VERSION 5.7 ;
  NOWIREEXTENSIONATPIN ON ;
  DIVIDERCHAR "/" ;
  BUSBITCHARS "[]" ;
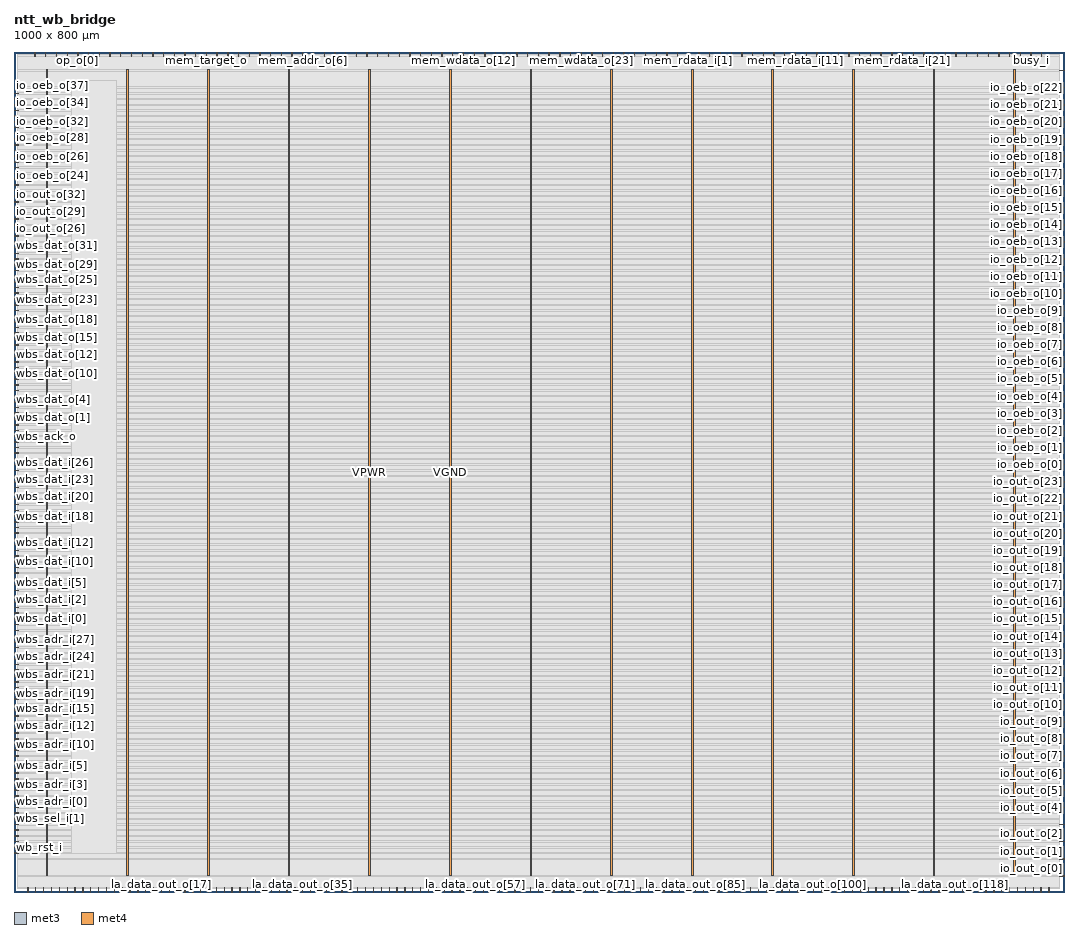
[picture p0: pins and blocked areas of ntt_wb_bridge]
MACRO ntt_wb_bridge
  CLASS BLOCK ;
  FOREIGN ntt_wb_bridge ;
  ORIGIN 0.000 0.000 ;
  SIZE 1000.000 BY 800.000 ;
  PIN VGND
    DIRECTION INOUT ;
    USE GROUND ;
    PORT
      LAYER met3 ;
        RECT 30.110 796.000 30.410 800.000 ;
    END
    PORT
      LAYER met4 ;
        RECT 107.500 16.080 109.100 783.600 ;
    END
    PORT
      LAYER met4 ;
        RECT 261.100 16.080 262.700 783.600 ;
    END
    PORT
      LAYER met4 ;
        RECT 414.700 16.080 416.300 783.600 ;
    END
    PORT
      LAYER met4 ;
        RECT 568.300 16.080 569.900 783.600 ;
    END
    PORT
      LAYER met4 ;
        RECT 721.900 16.080 723.500 783.600 ;
    END
    PORT
      LAYER met4 ;
        RECT 875.500 16.080 877.100 783.600 ;
    END
  END VGND
  PIN VPWR
    DIRECTION INOUT ;
    USE POWER ;
    PORT
      LAYER met3 ;
        RECT 19.910 796.000 20.210 800.000 ;
    END
    PORT
      LAYER met4 ;
        RECT 30.700 16.080 32.300 783.600 ;
    END
    PORT
      LAYER met4 ;
        RECT 184.300 16.080 185.900 783.600 ;
    END
    PORT
      LAYER met4 ;
        RECT 337.900 16.080 339.500 783.600 ;
    END
    PORT
      LAYER met4 ;
        RECT 491.500 16.080 493.100 783.600 ;
    END
    PORT
      LAYER met4 ;
        RECT 645.100 16.080 646.700 783.600 ;
    END
    PORT
      LAYER met4 ;
        RECT 798.700 16.080 800.300 783.600 ;
    END
    PORT
      LAYER met4 ;
        RECT 952.300 16.080 953.900 783.600 ;
    END
  END VPWR
  PIN busy_i
    DIRECTION INPUT ;
    USE SIGNAL ;
    ANTENNAGATEAREA 0.196500 ;
    ANTENNADIFFAREA 0.434700 ;
    PORT
      LAYER met3 ;
        RECT 968.510 796.000 968.810 800.000 ;
    END
  END busy_i
  PIN done_i
    DIRECTION INPUT ;
    USE SIGNAL ;
    ANTENNAGATEAREA 0.196500 ;
    ANTENNADIFFAREA 0.434700 ;
    PORT
      LAYER met3 ;
        RECT 978.710 796.000 979.010 800.000 ;
    END
  END done_i
  PIN engine_rst_n_o
    DIRECTION OUTPUT TRISTATE ;
    USE SIGNAL ;
    ANTENNADIFFAREA 3.180800 ;
    PORT
      LAYER met3 ;
        RECT 50.510 796.000 50.810 800.000 ;
    END
  END engine_rst_n_o
  PIN io_oeb_o[0]
    DIRECTION OUTPUT TRISTATE ;
    USE SIGNAL ;
    PORT
      LAYER met3 ;
        RECT 996.000 406.680 1000.000 407.280 ;
    END
  END io_oeb_o[0]
  PIN io_oeb_o[10]
    DIRECTION OUTPUT TRISTATE ;
    USE SIGNAL ;
    PORT
      LAYER met3 ;
        RECT 996.000 569.880 1000.000 570.480 ;
    END
  END io_oeb_o[10]
  PIN io_oeb_o[11]
    DIRECTION OUTPUT TRISTATE ;
    USE SIGNAL ;
    PORT
      LAYER met3 ;
        RECT 996.000 586.200 1000.000 586.800 ;
    END
  END io_oeb_o[11]
  PIN io_oeb_o[12]
    DIRECTION OUTPUT TRISTATE ;
    USE SIGNAL ;
    PORT
      LAYER met3 ;
        RECT 996.000 602.520 1000.000 603.120 ;
    END
  END io_oeb_o[12]
  PIN io_oeb_o[13]
    DIRECTION OUTPUT TRISTATE ;
    USE SIGNAL ;
    PORT
      LAYER met3 ;
        RECT 996.000 618.840 1000.000 619.440 ;
    END
  END io_oeb_o[13]
  PIN io_oeb_o[14]
    DIRECTION OUTPUT TRISTATE ;
    USE SIGNAL ;
    PORT
      LAYER met3 ;
        RECT 996.000 635.160 1000.000 635.760 ;
    END
  END io_oeb_o[14]
  PIN io_oeb_o[15]
    DIRECTION OUTPUT TRISTATE ;
    USE SIGNAL ;
    PORT
      LAYER met3 ;
        RECT 996.000 651.480 1000.000 652.080 ;
    END
  END io_oeb_o[15]
  PIN io_oeb_o[16]
    DIRECTION OUTPUT TRISTATE ;
    USE SIGNAL ;
    PORT
      LAYER met3 ;
        RECT 996.000 667.800 1000.000 668.400 ;
    END
  END io_oeb_o[16]
  PIN io_oeb_o[17]
    DIRECTION OUTPUT TRISTATE ;
    USE SIGNAL ;
    PORT
      LAYER met3 ;
        RECT 996.000 684.120 1000.000 684.720 ;
    END
  END io_oeb_o[17]
  PIN io_oeb_o[18]
    DIRECTION OUTPUT TRISTATE ;
    USE SIGNAL ;
    PORT
      LAYER met3 ;
        RECT 996.000 700.440 1000.000 701.040 ;
    END
  END io_oeb_o[18]
  PIN io_oeb_o[19]
    DIRECTION OUTPUT TRISTATE ;
    USE SIGNAL ;
    PORT
      LAYER met3 ;
        RECT 996.000 716.760 1000.000 717.360 ;
    END
  END io_oeb_o[19]
  PIN io_oeb_o[1]
    DIRECTION OUTPUT TRISTATE ;
    USE SIGNAL ;
    PORT
      LAYER met3 ;
        RECT 996.000 423.000 1000.000 423.600 ;
    END
  END io_oeb_o[1]
  PIN io_oeb_o[20]
    DIRECTION OUTPUT TRISTATE ;
    USE SIGNAL ;
    PORT
      LAYER met3 ;
        RECT 996.000 733.080 1000.000 733.680 ;
    END
  END io_oeb_o[20]
  PIN io_oeb_o[21]
    DIRECTION OUTPUT TRISTATE ;
    USE SIGNAL ;
    PORT
      LAYER met3 ;
        RECT 996.000 749.400 1000.000 750.000 ;
    END
  END io_oeb_o[21]
  PIN io_oeb_o[22]
    DIRECTION OUTPUT TRISTATE ;
    USE SIGNAL ;
    PORT
      LAYER met3 ;
        RECT 996.000 765.720 1000.000 766.320 ;
    END
  END io_oeb_o[22]
  PIN io_oeb_o[23]
    DIRECTION OUTPUT TRISTATE ;
    USE SIGNAL ;
    PORT
      LAYER met3 ;
        RECT 996.000 782.040 1000.000 782.640 ;
    END
  END io_oeb_o[23]
  PIN io_oeb_o[24]
    DIRECTION OUTPUT TRISTATE ;
    USE SIGNAL ;
    PORT
      LAYER met3 ;
        RECT 0.000 689.560 4.000 690.160 ;
    END
  END io_oeb_o[24]
  PIN io_oeb_o[25]
    DIRECTION OUTPUT TRISTATE ;
    USE SIGNAL ;
    PORT
      LAYER met3 ;
        RECT 0.000 695.000 4.000 695.600 ;
    END
  END io_oeb_o[25]
  PIN io_oeb_o[26]
    DIRECTION OUTPUT TRISTATE ;
    USE SIGNAL ;
    PORT
      LAYER met3 ;
        RECT 0.000 700.440 4.000 701.040 ;
    END
  END io_oeb_o[26]
  PIN io_oeb_o[27]
    DIRECTION OUTPUT TRISTATE ;
    USE SIGNAL ;
    PORT
      LAYER met3 ;
        RECT 0.000 705.880 4.000 706.480 ;
    END
  END io_oeb_o[27]
  PIN io_oeb_o[28]
    DIRECTION OUTPUT TRISTATE ;
    USE SIGNAL ;
    PORT
      LAYER met3 ;
        RECT 0.000 711.320 4.000 711.920 ;
    END
  END io_oeb_o[28]
  PIN io_oeb_o[29]
    DIRECTION OUTPUT TRISTATE ;
    USE SIGNAL ;
    PORT
      LAYER met3 ;
        RECT 0.000 716.760 4.000 717.360 ;
    END
  END io_oeb_o[29]
  PIN io_oeb_o[2]
    DIRECTION OUTPUT TRISTATE ;
    USE SIGNAL ;
    PORT
      LAYER met3 ;
        RECT 996.000 439.320 1000.000 439.920 ;
    END
  END io_oeb_o[2]
  PIN io_oeb_o[30]
    DIRECTION OUTPUT TRISTATE ;
    USE SIGNAL ;
    PORT
      LAYER met3 ;
        RECT 0.000 722.200 4.000 722.800 ;
    END
  END io_oeb_o[30]
  PIN io_oeb_o[31]
    DIRECTION OUTPUT TRISTATE ;
    USE SIGNAL ;
    PORT
      LAYER met3 ;
        RECT 0.000 727.640 4.000 728.240 ;
    END
  END io_oeb_o[31]
  PIN io_oeb_o[32]
    DIRECTION OUTPUT TRISTATE ;
    USE SIGNAL ;
    PORT
      LAYER met3 ;
        RECT 0.000 733.080 4.000 733.680 ;
    END
  END io_oeb_o[32]
  PIN io_oeb_o[33]
    DIRECTION OUTPUT TRISTATE ;
    USE SIGNAL ;
    PORT
      LAYER met3 ;
        RECT 0.000 738.520 4.000 739.120 ;
    END
  END io_oeb_o[33]
  PIN io_oeb_o[34]
    DIRECTION OUTPUT TRISTATE ;
    USE SIGNAL ;
    PORT
      LAYER met3 ;
        RECT 0.000 743.960 4.000 744.560 ;
    END
  END io_oeb_o[34]
  PIN io_oeb_o[35]
    DIRECTION OUTPUT TRISTATE ;
    USE SIGNAL ;
    PORT
      LAYER met3 ;
        RECT 0.000 749.400 4.000 750.000 ;
    END
  END io_oeb_o[35]
  PIN io_oeb_o[36]
    DIRECTION OUTPUT TRISTATE ;
    USE SIGNAL ;
    PORT
      LAYER met3 ;
        RECT 0.000 754.840 4.000 755.440 ;
    END
  END io_oeb_o[36]
  PIN io_oeb_o[37]
    DIRECTION OUTPUT TRISTATE ;
    USE SIGNAL ;
    PORT
      LAYER met3 ;
        RECT 0.000 760.280 4.000 760.880 ;
    END
  END io_oeb_o[37]
  PIN io_oeb_o[3]
    DIRECTION OUTPUT TRISTATE ;
    USE SIGNAL ;
    PORT
      LAYER met3 ;
        RECT 996.000 455.640 1000.000 456.240 ;
    END
  END io_oeb_o[3]
  PIN io_oeb_o[4]
    DIRECTION OUTPUT TRISTATE ;
    USE SIGNAL ;
    PORT
      LAYER met3 ;
        RECT 996.000 471.960 1000.000 472.560 ;
    END
  END io_oeb_o[4]
  PIN io_oeb_o[5]
    DIRECTION OUTPUT TRISTATE ;
    USE SIGNAL ;
    PORT
      LAYER met3 ;
        RECT 996.000 488.280 1000.000 488.880 ;
    END
  END io_oeb_o[5]
  PIN io_oeb_o[6]
    DIRECTION OUTPUT TRISTATE ;
    USE SIGNAL ;
    PORT
      LAYER met3 ;
        RECT 996.000 504.600 1000.000 505.200 ;
    END
  END io_oeb_o[6]
  PIN io_oeb_o[7]
    DIRECTION OUTPUT TRISTATE ;
    USE SIGNAL ;
    PORT
      LAYER met3 ;
        RECT 996.000 520.920 1000.000 521.520 ;
    END
  END io_oeb_o[7]
  PIN io_oeb_o[8]
    DIRECTION OUTPUT TRISTATE ;
    USE SIGNAL ;
    PORT
      LAYER met3 ;
        RECT 996.000 537.240 1000.000 537.840 ;
    END
  END io_oeb_o[8]
  PIN io_oeb_o[9]
    DIRECTION OUTPUT TRISTATE ;
    USE SIGNAL ;
    PORT
      LAYER met3 ;
        RECT 996.000 553.560 1000.000 554.160 ;
    END
  END io_oeb_o[9]
  PIN io_out_o[0]
    DIRECTION OUTPUT TRISTATE ;
    USE SIGNAL ;
    PORT
      LAYER met3 ;
        RECT 996.000 15.000 1000.000 15.600 ;
    END
  END io_out_o[0]
  PIN io_out_o[10]
    DIRECTION OUTPUT TRISTATE ;
    USE SIGNAL ;
    PORT
      LAYER met3 ;
        RECT 996.000 178.200 1000.000 178.800 ;
    END
  END io_out_o[10]
  PIN io_out_o[11]
    DIRECTION OUTPUT TRISTATE ;
    USE SIGNAL ;
    PORT
      LAYER met3 ;
        RECT 996.000 194.520 1000.000 195.120 ;
    END
  END io_out_o[11]
  PIN io_out_o[12]
    DIRECTION OUTPUT TRISTATE ;
    USE SIGNAL ;
    PORT
      LAYER met3 ;
        RECT 996.000 210.840 1000.000 211.440 ;
    END
  END io_out_o[12]
  PIN io_out_o[13]
    DIRECTION OUTPUT TRISTATE ;
    USE SIGNAL ;
    PORT
      LAYER met3 ;
        RECT 996.000 227.160 1000.000 227.760 ;
    END
  END io_out_o[13]
  PIN io_out_o[14]
    DIRECTION OUTPUT TRISTATE ;
    USE SIGNAL ;
    PORT
      LAYER met3 ;
        RECT 996.000 243.480 1000.000 244.080 ;
    END
  END io_out_o[14]
  PIN io_out_o[15]
    DIRECTION OUTPUT TRISTATE ;
    USE SIGNAL ;
    PORT
      LAYER met3 ;
        RECT 996.000 259.800 1000.000 260.400 ;
    END
  END io_out_o[15]
  PIN io_out_o[16]
    DIRECTION OUTPUT TRISTATE ;
    USE SIGNAL ;
    PORT
      LAYER met3 ;
        RECT 996.000 276.120 1000.000 276.720 ;
    END
  END io_out_o[16]
  PIN io_out_o[17]
    DIRECTION OUTPUT TRISTATE ;
    USE SIGNAL ;
    PORT
      LAYER met3 ;
        RECT 996.000 292.440 1000.000 293.040 ;
    END
  END io_out_o[17]
  PIN io_out_o[18]
    DIRECTION OUTPUT TRISTATE ;
    USE SIGNAL ;
    PORT
      LAYER met3 ;
        RECT 996.000 308.760 1000.000 309.360 ;
    END
  END io_out_o[18]
  PIN io_out_o[19]
    DIRECTION OUTPUT TRISTATE ;
    USE SIGNAL ;
    PORT
      LAYER met3 ;
        RECT 996.000 325.080 1000.000 325.680 ;
    END
  END io_out_o[19]
  PIN io_out_o[1]
    DIRECTION OUTPUT TRISTATE ;
    USE SIGNAL ;
    PORT
      LAYER met3 ;
        RECT 996.000 31.320 1000.000 31.920 ;
    END
  END io_out_o[1]
  PIN io_out_o[20]
    DIRECTION OUTPUT TRISTATE ;
    USE SIGNAL ;
    PORT
      LAYER met3 ;
        RECT 996.000 341.400 1000.000 342.000 ;
    END
  END io_out_o[20]
  PIN io_out_o[21]
    DIRECTION OUTPUT TRISTATE ;
    USE SIGNAL ;
    PORT
      LAYER met3 ;
        RECT 996.000 357.720 1000.000 358.320 ;
    END
  END io_out_o[21]
  PIN io_out_o[22]
    DIRECTION OUTPUT TRISTATE ;
    USE SIGNAL ;
    PORT
      LAYER met3 ;
        RECT 996.000 374.040 1000.000 374.640 ;
    END
  END io_out_o[22]
  PIN io_out_o[23]
    DIRECTION OUTPUT TRISTATE ;
    USE SIGNAL ;
    PORT
      LAYER met3 ;
        RECT 996.000 390.360 1000.000 390.960 ;
    END
  END io_out_o[23]
  PIN io_out_o[24]
    DIRECTION OUTPUT TRISTATE ;
    USE SIGNAL ;
    PORT
      LAYER met3 ;
        RECT 0.000 613.400 4.000 614.000 ;
    END
  END io_out_o[24]
  PIN io_out_o[25]
    DIRECTION OUTPUT TRISTATE ;
    USE SIGNAL ;
    PORT
      LAYER met3 ;
        RECT 0.000 618.840 4.000 619.440 ;
    END
  END io_out_o[25]
  PIN io_out_o[26]
    DIRECTION OUTPUT TRISTATE ;
    USE SIGNAL ;
    PORT
      LAYER met3 ;
        RECT 0.000 624.280 4.000 624.880 ;
    END
  END io_out_o[26]
  PIN io_out_o[27]
    DIRECTION OUTPUT TRISTATE ;
    USE SIGNAL ;
    PORT
      LAYER met3 ;
        RECT 0.000 629.720 4.000 630.320 ;
    END
  END io_out_o[27]
  PIN io_out_o[28]
    DIRECTION OUTPUT TRISTATE ;
    USE SIGNAL ;
    PORT
      LAYER met3 ;
        RECT 0.000 635.160 4.000 635.760 ;
    END
  END io_out_o[28]
  PIN io_out_o[29]
    DIRECTION OUTPUT TRISTATE ;
    USE SIGNAL ;
    PORT
      LAYER met3 ;
        RECT 0.000 640.600 4.000 641.200 ;
    END
  END io_out_o[29]
  PIN io_out_o[2]
    DIRECTION OUTPUT TRISTATE ;
    USE SIGNAL ;
    PORT
      LAYER met3 ;
        RECT 996.000 47.640 1000.000 48.240 ;
    END
  END io_out_o[2]
  PIN io_out_o[30]
    DIRECTION OUTPUT TRISTATE ;
    USE SIGNAL ;
    PORT
      LAYER met3 ;
        RECT 0.000 646.040 4.000 646.640 ;
    END
  END io_out_o[30]
  PIN io_out_o[31]
    DIRECTION OUTPUT TRISTATE ;
    USE SIGNAL ;
    PORT
      LAYER met3 ;
        RECT 0.000 651.480 4.000 652.080 ;
    END
  END io_out_o[31]
  PIN io_out_o[32]
    DIRECTION OUTPUT TRISTATE ;
    USE SIGNAL ;
    PORT
      LAYER met3 ;
        RECT 0.000 656.920 4.000 657.520 ;
    END
  END io_out_o[32]
  PIN io_out_o[33]
    DIRECTION OUTPUT TRISTATE ;
    USE SIGNAL ;
    PORT
      LAYER met3 ;
        RECT 0.000 662.360 4.000 662.960 ;
    END
  END io_out_o[33]
  PIN io_out_o[34]
    DIRECTION OUTPUT TRISTATE ;
    USE SIGNAL ;
    PORT
      LAYER met3 ;
        RECT 0.000 667.800 4.000 668.400 ;
    END
  END io_out_o[34]
  PIN io_out_o[35]
    DIRECTION OUTPUT TRISTATE ;
    USE SIGNAL ;
    PORT
      LAYER met3 ;
        RECT 0.000 673.240 4.000 673.840 ;
    END
  END io_out_o[35]
  PIN io_out_o[36]
    DIRECTION OUTPUT TRISTATE ;
    USE SIGNAL ;
    PORT
      LAYER met3 ;
        RECT 0.000 678.680 4.000 679.280 ;
    END
  END io_out_o[36]
  PIN io_out_o[37]
    DIRECTION OUTPUT TRISTATE ;
    USE SIGNAL ;
    PORT
      LAYER met3 ;
        RECT 0.000 684.120 4.000 684.720 ;
    END
  END io_out_o[37]
  PIN io_out_o[3]
    DIRECTION OUTPUT TRISTATE ;
    USE SIGNAL ;
    PORT
      LAYER met3 ;
        RECT 996.000 63.960 1000.000 64.560 ;
    END
  END io_out_o[3]
  PIN io_out_o[4]
    DIRECTION OUTPUT TRISTATE ;
    USE SIGNAL ;
    PORT
      LAYER met3 ;
        RECT 996.000 80.280 1000.000 80.880 ;
    END
  END io_out_o[4]
  PIN io_out_o[5]
    DIRECTION OUTPUT TRISTATE ;
    USE SIGNAL ;
    PORT
      LAYER met3 ;
        RECT 996.000 96.600 1000.000 97.200 ;
    END
  END io_out_o[5]
  PIN io_out_o[6]
    DIRECTION OUTPUT TRISTATE ;
    USE SIGNAL ;
    PORT
      LAYER met3 ;
        RECT 996.000 112.920 1000.000 113.520 ;
    END
  END io_out_o[6]
  PIN io_out_o[7]
    DIRECTION OUTPUT TRISTATE ;
    USE SIGNAL ;
    PORT
      LAYER met3 ;
        RECT 996.000 129.240 1000.000 129.840 ;
    END
  END io_out_o[7]
  PIN io_out_o[8]
    DIRECTION OUTPUT TRISTATE ;
    USE SIGNAL ;
    PORT
      LAYER met3 ;
        RECT 996.000 145.560 1000.000 146.160 ;
    END
  END io_out_o[8]
  PIN io_out_o[9]
    DIRECTION OUTPUT TRISTATE ;
    USE SIGNAL ;
    PORT
      LAYER met3 ;
        RECT 996.000 161.880 1000.000 162.480 ;
    END
  END io_out_o[9]
  PIN la_data_out_o[0]
    DIRECTION OUTPUT TRISTATE ;
    USE SIGNAL ;
    ANTENNADIFFAREA 3.180800 ;
    PORT
      LAYER met3 ;
        RECT 13.110 0.000 13.410 4.000 ;
    END
  END la_data_out_o[0]
  PIN la_data_out_o[100]
    DIRECTION OUTPUT TRISTATE ;
    USE SIGNAL ;
    PORT
      LAYER met3 ;
        RECT 761.110 0.000 761.410 4.000 ;
    END
  END la_data_out_o[100]
  PIN la_data_out_o[101]
    DIRECTION OUTPUT TRISTATE ;
    USE SIGNAL ;
    PORT
      LAYER met3 ;
        RECT 768.590 0.000 768.890 4.000 ;
    END
  END la_data_out_o[101]
  PIN la_data_out_o[102]
    DIRECTION OUTPUT TRISTATE ;
    USE SIGNAL ;
    PORT
      LAYER met3 ;
        RECT 776.070 0.000 776.370 4.000 ;
    END
  END la_data_out_o[102]
  PIN la_data_out_o[103]
    DIRECTION OUTPUT TRISTATE ;
    USE SIGNAL ;
    PORT
      LAYER met3 ;
        RECT 783.550 0.000 783.850 4.000 ;
    END
  END la_data_out_o[103]
  PIN la_data_out_o[104]
    DIRECTION OUTPUT TRISTATE ;
    USE SIGNAL ;
    PORT
      LAYER met3 ;
        RECT 791.030 0.000 791.330 4.000 ;
    END
  END la_data_out_o[104]
  PIN la_data_out_o[105]
    DIRECTION OUTPUT TRISTATE ;
    USE SIGNAL ;
    PORT
      LAYER met3 ;
        RECT 798.510 0.000 798.810 4.000 ;
    END
  END la_data_out_o[105]
  PIN la_data_out_o[106]
    DIRECTION OUTPUT TRISTATE ;
    USE SIGNAL ;
    PORT
      LAYER met3 ;
        RECT 805.990 0.000 806.290 4.000 ;
    END
  END la_data_out_o[106]
  PIN la_data_out_o[107]
    DIRECTION OUTPUT TRISTATE ;
    USE SIGNAL ;
    PORT
      LAYER met3 ;
        RECT 813.470 0.000 813.770 4.000 ;
    END
  END la_data_out_o[107]
  PIN la_data_out_o[108]
    DIRECTION OUTPUT TRISTATE ;
    USE SIGNAL ;
    PORT
      LAYER met3 ;
        RECT 820.950 0.000 821.250 4.000 ;
    END
  END la_data_out_o[108]
  PIN la_data_out_o[109]
    DIRECTION OUTPUT TRISTATE ;
    USE SIGNAL ;
    PORT
      LAYER met3 ;
        RECT 828.430 0.000 828.730 4.000 ;
    END
  END la_data_out_o[109]
  PIN la_data_out_o[10]
    DIRECTION OUTPUT TRISTATE ;
    USE SIGNAL ;
    PORT
      LAYER met3 ;
        RECT 87.910 0.000 88.210 4.000 ;
    END
  END la_data_out_o[10]
  PIN la_data_out_o[110]
    DIRECTION OUTPUT TRISTATE ;
    USE SIGNAL ;
    PORT
      LAYER met3 ;
        RECT 835.910 0.000 836.210 4.000 ;
    END
  END la_data_out_o[110]
  PIN la_data_out_o[111]
    DIRECTION OUTPUT TRISTATE ;
    USE SIGNAL ;
    PORT
      LAYER met3 ;
        RECT 843.390 0.000 843.690 4.000 ;
    END
  END la_data_out_o[111]
  PIN la_data_out_o[112]
    DIRECTION OUTPUT TRISTATE ;
    USE SIGNAL ;
    PORT
      LAYER met3 ;
        RECT 850.870 0.000 851.170 4.000 ;
    END
  END la_data_out_o[112]
  PIN la_data_out_o[113]
    DIRECTION OUTPUT TRISTATE ;
    USE SIGNAL ;
    PORT
      LAYER met3 ;
        RECT 858.350 0.000 858.650 4.000 ;
    END
  END la_data_out_o[113]
  PIN la_data_out_o[114]
    DIRECTION OUTPUT TRISTATE ;
    USE SIGNAL ;
    PORT
      LAYER met3 ;
        RECT 865.830 0.000 866.130 4.000 ;
    END
  END la_data_out_o[114]
  PIN la_data_out_o[115]
    DIRECTION OUTPUT TRISTATE ;
    USE SIGNAL ;
    PORT
      LAYER met3 ;
        RECT 873.310 0.000 873.610 4.000 ;
    END
  END la_data_out_o[115]
  PIN la_data_out_o[116]
    DIRECTION OUTPUT TRISTATE ;
    USE SIGNAL ;
    PORT
      LAYER met3 ;
        RECT 880.790 0.000 881.090 4.000 ;
    END
  END la_data_out_o[116]
  PIN la_data_out_o[117]
    DIRECTION OUTPUT TRISTATE ;
    USE SIGNAL ;
    PORT
      LAYER met3 ;
        RECT 888.270 0.000 888.570 4.000 ;
    END
  END la_data_out_o[117]
  PIN la_data_out_o[118]
    DIRECTION OUTPUT TRISTATE ;
    USE SIGNAL ;
    PORT
      LAYER met3 ;
        RECT 895.750 0.000 896.050 4.000 ;
    END
  END la_data_out_o[118]
  PIN la_data_out_o[119]
    DIRECTION OUTPUT TRISTATE ;
    USE SIGNAL ;
    PORT
      LAYER met3 ;
        RECT 903.230 0.000 903.530 4.000 ;
    END
  END la_data_out_o[119]
  PIN la_data_out_o[11]
    DIRECTION OUTPUT TRISTATE ;
    USE SIGNAL ;
    PORT
      LAYER met3 ;
        RECT 95.390 0.000 95.690 4.000 ;
    END
  END la_data_out_o[11]
  PIN la_data_out_o[120]
    DIRECTION OUTPUT TRISTATE ;
    USE SIGNAL ;
    PORT
      LAYER met3 ;
        RECT 910.710 0.000 911.010 4.000 ;
    END
  END la_data_out_o[120]
  PIN la_data_out_o[121]
    DIRECTION OUTPUT TRISTATE ;
    USE SIGNAL ;
    PORT
      LAYER met3 ;
        RECT 918.190 0.000 918.490 4.000 ;
    END
  END la_data_out_o[121]
  PIN la_data_out_o[122]
    DIRECTION OUTPUT TRISTATE ;
    USE SIGNAL ;
    PORT
      LAYER met3 ;
        RECT 925.670 0.000 925.970 4.000 ;
    END
  END la_data_out_o[122]
  PIN la_data_out_o[123]
    DIRECTION OUTPUT TRISTATE ;
    USE SIGNAL ;
    PORT
      LAYER met3 ;
        RECT 933.150 0.000 933.450 4.000 ;
    END
  END la_data_out_o[123]
  PIN la_data_out_o[124]
    DIRECTION OUTPUT TRISTATE ;
    USE SIGNAL ;
    PORT
      LAYER met3 ;
        RECT 940.630 0.000 940.930 4.000 ;
    END
  END la_data_out_o[124]
  PIN la_data_out_o[125]
    DIRECTION OUTPUT TRISTATE ;
    USE SIGNAL ;
    PORT
      LAYER met3 ;
        RECT 948.110 0.000 948.410 4.000 ;
    END
  END la_data_out_o[125]
  PIN la_data_out_o[126]
    DIRECTION OUTPUT TRISTATE ;
    USE SIGNAL ;
    PORT
      LAYER met3 ;
        RECT 955.590 0.000 955.890 4.000 ;
    END
  END la_data_out_o[126]
  PIN la_data_out_o[127]
    DIRECTION OUTPUT TRISTATE ;
    USE SIGNAL ;
    PORT
      LAYER met3 ;
        RECT 963.070 0.000 963.370 4.000 ;
    END
  END la_data_out_o[127]
  PIN la_data_out_o[12]
    DIRECTION OUTPUT TRISTATE ;
    USE SIGNAL ;
    PORT
      LAYER met3 ;
        RECT 102.870 0.000 103.170 4.000 ;
    END
  END la_data_out_o[12]
  PIN la_data_out_o[13]
    DIRECTION OUTPUT TRISTATE ;
    USE SIGNAL ;
    PORT
      LAYER met3 ;
        RECT 110.350 0.000 110.650 4.000 ;
    END
  END la_data_out_o[13]
  PIN la_data_out_o[14]
    DIRECTION OUTPUT TRISTATE ;
    USE SIGNAL ;
    PORT
      LAYER met3 ;
        RECT 117.830 0.000 118.130 4.000 ;
    END
  END la_data_out_o[14]
  PIN la_data_out_o[15]
    DIRECTION OUTPUT TRISTATE ;
    USE SIGNAL ;
    PORT
      LAYER met3 ;
        RECT 125.310 0.000 125.610 4.000 ;
    END
  END la_data_out_o[15]
  PIN la_data_out_o[16]
    DIRECTION OUTPUT TRISTATE ;
    USE SIGNAL ;
    PORT
      LAYER met3 ;
        RECT 132.790 0.000 133.090 4.000 ;
    END
  END la_data_out_o[16]
  PIN la_data_out_o[17]
    DIRECTION OUTPUT TRISTATE ;
    USE SIGNAL ;
    PORT
      LAYER met3 ;
        RECT 140.270 0.000 140.570 4.000 ;
    END
  END la_data_out_o[17]
  PIN la_data_out_o[18]
    DIRECTION OUTPUT TRISTATE ;
    USE SIGNAL ;
    PORT
      LAYER met3 ;
        RECT 147.750 0.000 148.050 4.000 ;
    END
  END la_data_out_o[18]
  PIN la_data_out_o[19]
    DIRECTION OUTPUT TRISTATE ;
    USE SIGNAL ;
    PORT
      LAYER met3 ;
        RECT 155.230 0.000 155.530 4.000 ;
    END
  END la_data_out_o[19]
  PIN la_data_out_o[1]
    DIRECTION OUTPUT TRISTATE ;
    USE SIGNAL ;
    ANTENNADIFFAREA 3.180800 ;
    PORT
      LAYER met3 ;
        RECT 20.590 0.000 20.890 4.000 ;
    END
  END la_data_out_o[1]
  PIN la_data_out_o[20]
    DIRECTION OUTPUT TRISTATE ;
    USE SIGNAL ;
    PORT
      LAYER met3 ;
        RECT 162.710 0.000 163.010 4.000 ;
    END
  END la_data_out_o[20]
  PIN la_data_out_o[21]
    DIRECTION OUTPUT TRISTATE ;
    USE SIGNAL ;
    PORT
      LAYER met3 ;
        RECT 170.190 0.000 170.490 4.000 ;
    END
  END la_data_out_o[21]
  PIN la_data_out_o[22]
    DIRECTION OUTPUT TRISTATE ;
    USE SIGNAL ;
    PORT
      LAYER met3 ;
        RECT 177.670 0.000 177.970 4.000 ;
    END
  END la_data_out_o[22]
  PIN la_data_out_o[23]
    DIRECTION OUTPUT TRISTATE ;
    USE SIGNAL ;
    PORT
      LAYER met3 ;
        RECT 185.150 0.000 185.450 4.000 ;
    END
  END la_data_out_o[23]
  PIN la_data_out_o[24]
    DIRECTION OUTPUT TRISTATE ;
    USE SIGNAL ;
    PORT
      LAYER met3 ;
        RECT 192.630 0.000 192.930 4.000 ;
    END
  END la_data_out_o[24]
  PIN la_data_out_o[25]
    DIRECTION OUTPUT TRISTATE ;
    USE SIGNAL ;
    PORT
      LAYER met3 ;
        RECT 200.110 0.000 200.410 4.000 ;
    END
  END la_data_out_o[25]
  PIN la_data_out_o[26]
    DIRECTION OUTPUT TRISTATE ;
    USE SIGNAL ;
    PORT
      LAYER met3 ;
        RECT 207.590 0.000 207.890 4.000 ;
    END
  END la_data_out_o[26]
  PIN la_data_out_o[27]
    DIRECTION OUTPUT TRISTATE ;
    USE SIGNAL ;
    PORT
      LAYER met3 ;
        RECT 215.070 0.000 215.370 4.000 ;
    END
  END la_data_out_o[27]
  PIN la_data_out_o[28]
    DIRECTION OUTPUT TRISTATE ;
    USE SIGNAL ;
    PORT
      LAYER met3 ;
        RECT 222.550 0.000 222.850 4.000 ;
    END
  END la_data_out_o[28]
  PIN la_data_out_o[29]
    DIRECTION OUTPUT TRISTATE ;
    USE SIGNAL ;
    PORT
      LAYER met3 ;
        RECT 230.030 0.000 230.330 4.000 ;
    END
  END la_data_out_o[29]
  PIN la_data_out_o[2]
    DIRECTION OUTPUT TRISTATE ;
    USE SIGNAL ;
    ANTENNADIFFAREA 3.180800 ;
    PORT
      LAYER met3 ;
        RECT 28.070 0.000 28.370 4.000 ;
    END
  END la_data_out_o[2]
  PIN la_data_out_o[30]
    DIRECTION OUTPUT TRISTATE ;
    USE SIGNAL ;
    PORT
      LAYER met3 ;
        RECT 237.510 0.000 237.810 4.000 ;
    END
  END la_data_out_o[30]
  PIN la_data_out_o[31]
    DIRECTION OUTPUT TRISTATE ;
    USE SIGNAL ;
    PORT
      LAYER met3 ;
        RECT 244.990 0.000 245.290 4.000 ;
    END
  END la_data_out_o[31]
  PIN la_data_out_o[32]
    DIRECTION OUTPUT TRISTATE ;
    USE SIGNAL ;
    PORT
      LAYER met3 ;
        RECT 252.470 0.000 252.770 4.000 ;
    END
  END la_data_out_o[32]
  PIN la_data_out_o[33]
    DIRECTION OUTPUT TRISTATE ;
    USE SIGNAL ;
    PORT
      LAYER met3 ;
        RECT 259.950 0.000 260.250 4.000 ;
    END
  END la_data_out_o[33]
  PIN la_data_out_o[34]
    DIRECTION OUTPUT TRISTATE ;
    USE SIGNAL ;
    PORT
      LAYER met3 ;
        RECT 267.430 0.000 267.730 4.000 ;
    END
  END la_data_out_o[34]
  PIN la_data_out_o[35]
    DIRECTION OUTPUT TRISTATE ;
    USE SIGNAL ;
    PORT
      LAYER met3 ;
        RECT 274.910 0.000 275.210 4.000 ;
    END
  END la_data_out_o[35]
  PIN la_data_out_o[36]
    DIRECTION OUTPUT TRISTATE ;
    USE SIGNAL ;
    PORT
      LAYER met3 ;
        RECT 282.390 0.000 282.690 4.000 ;
    END
  END la_data_out_o[36]
  PIN la_data_out_o[37]
    DIRECTION OUTPUT TRISTATE ;
    USE SIGNAL ;
    PORT
      LAYER met3 ;
        RECT 289.870 0.000 290.170 4.000 ;
    END
  END la_data_out_o[37]
  PIN la_data_out_o[38]
    DIRECTION OUTPUT TRISTATE ;
    USE SIGNAL ;
    PORT
      LAYER met3 ;
        RECT 297.350 0.000 297.650 4.000 ;
    END
  END la_data_out_o[38]
  PIN la_data_out_o[39]
    DIRECTION OUTPUT TRISTATE ;
    USE SIGNAL ;
    PORT
      LAYER met3 ;
        RECT 304.830 0.000 305.130 4.000 ;
    END
  END la_data_out_o[39]
  PIN la_data_out_o[3]
    DIRECTION OUTPUT TRISTATE ;
    USE SIGNAL ;
    PORT
      LAYER met3 ;
        RECT 35.550 0.000 35.850 4.000 ;
    END
  END la_data_out_o[3]
  PIN la_data_out_o[40]
    DIRECTION OUTPUT TRISTATE ;
    USE SIGNAL ;
    PORT
      LAYER met3 ;
        RECT 312.310 0.000 312.610 4.000 ;
    END
  END la_data_out_o[40]
  PIN la_data_out_o[41]
    DIRECTION OUTPUT TRISTATE ;
    USE SIGNAL ;
    PORT
      LAYER met3 ;
        RECT 319.790 0.000 320.090 4.000 ;
    END
  END la_data_out_o[41]
  PIN la_data_out_o[42]
    DIRECTION OUTPUT TRISTATE ;
    USE SIGNAL ;
    PORT
      LAYER met3 ;
        RECT 327.270 0.000 327.570 4.000 ;
    END
  END la_data_out_o[42]
  PIN la_data_out_o[43]
    DIRECTION OUTPUT TRISTATE ;
    USE SIGNAL ;
    PORT
      LAYER met3 ;
        RECT 334.750 0.000 335.050 4.000 ;
    END
  END la_data_out_o[43]
  PIN la_data_out_o[44]
    DIRECTION OUTPUT TRISTATE ;
    USE SIGNAL ;
    PORT
      LAYER met3 ;
        RECT 342.230 0.000 342.530 4.000 ;
    END
  END la_data_out_o[44]
  PIN la_data_out_o[45]
    DIRECTION OUTPUT TRISTATE ;
    USE SIGNAL ;
    PORT
      LAYER met3 ;
        RECT 349.710 0.000 350.010 4.000 ;
    END
  END la_data_out_o[45]
  PIN la_data_out_o[46]
    DIRECTION OUTPUT TRISTATE ;
    USE SIGNAL ;
    PORT
      LAYER met3 ;
        RECT 357.190 0.000 357.490 4.000 ;
    END
  END la_data_out_o[46]
  PIN la_data_out_o[47]
    DIRECTION OUTPUT TRISTATE ;
    USE SIGNAL ;
    PORT
      LAYER met3 ;
        RECT 364.670 0.000 364.970 4.000 ;
    END
  END la_data_out_o[47]
  PIN la_data_out_o[48]
    DIRECTION OUTPUT TRISTATE ;
    USE SIGNAL ;
    PORT
      LAYER met3 ;
        RECT 372.150 0.000 372.450 4.000 ;
    END
  END la_data_out_o[48]
  PIN la_data_out_o[49]
    DIRECTION OUTPUT TRISTATE ;
    USE SIGNAL ;
    PORT
      LAYER met3 ;
        RECT 379.630 0.000 379.930 4.000 ;
    END
  END la_data_out_o[49]
  PIN la_data_out_o[4]
    DIRECTION OUTPUT TRISTATE ;
    USE SIGNAL ;
    PORT
      LAYER met3 ;
        RECT 43.030 0.000 43.330 4.000 ;
    END
  END la_data_out_o[4]
  PIN la_data_out_o[50]
    DIRECTION OUTPUT TRISTATE ;
    USE SIGNAL ;
    PORT
      LAYER met3 ;
        RECT 387.110 0.000 387.410 4.000 ;
    END
  END la_data_out_o[50]
  PIN la_data_out_o[51]
    DIRECTION OUTPUT TRISTATE ;
    USE SIGNAL ;
    PORT
      LAYER met3 ;
        RECT 394.590 0.000 394.890 4.000 ;
    END
  END la_data_out_o[51]
  PIN la_data_out_o[52]
    DIRECTION OUTPUT TRISTATE ;
    USE SIGNAL ;
    PORT
      LAYER met3 ;
        RECT 402.070 0.000 402.370 4.000 ;
    END
  END la_data_out_o[52]
  PIN la_data_out_o[53]
    DIRECTION OUTPUT TRISTATE ;
    USE SIGNAL ;
    PORT
      LAYER met3 ;
        RECT 409.550 0.000 409.850 4.000 ;
    END
  END la_data_out_o[53]
  PIN la_data_out_o[54]
    DIRECTION OUTPUT TRISTATE ;
    USE SIGNAL ;
    PORT
      LAYER met3 ;
        RECT 417.030 0.000 417.330 4.000 ;
    END
  END la_data_out_o[54]
  PIN la_data_out_o[55]
    DIRECTION OUTPUT TRISTATE ;
    USE SIGNAL ;
    PORT
      LAYER met3 ;
        RECT 424.510 0.000 424.810 4.000 ;
    END
  END la_data_out_o[55]
  PIN la_data_out_o[56]
    DIRECTION OUTPUT TRISTATE ;
    USE SIGNAL ;
    PORT
      LAYER met3 ;
        RECT 431.990 0.000 432.290 4.000 ;
    END
  END la_data_out_o[56]
  PIN la_data_out_o[57]
    DIRECTION OUTPUT TRISTATE ;
    USE SIGNAL ;
    PORT
      LAYER met3 ;
        RECT 439.470 0.000 439.770 4.000 ;
    END
  END la_data_out_o[57]
  PIN la_data_out_o[58]
    DIRECTION OUTPUT TRISTATE ;
    USE SIGNAL ;
    PORT
      LAYER met3 ;
        RECT 446.950 0.000 447.250 4.000 ;
    END
  END la_data_out_o[58]
  PIN la_data_out_o[59]
    DIRECTION OUTPUT TRISTATE ;
    USE SIGNAL ;
    PORT
      LAYER met3 ;
        RECT 454.430 0.000 454.730 4.000 ;
    END
  END la_data_out_o[59]
  PIN la_data_out_o[5]
    DIRECTION OUTPUT TRISTATE ;
    USE SIGNAL ;
    PORT
      LAYER met3 ;
        RECT 50.510 0.000 50.810 4.000 ;
    END
  END la_data_out_o[5]
  PIN la_data_out_o[60]
    DIRECTION OUTPUT TRISTATE ;
    USE SIGNAL ;
    PORT
      LAYER met3 ;
        RECT 461.910 0.000 462.210 4.000 ;
    END
  END la_data_out_o[60]
  PIN la_data_out_o[61]
    DIRECTION OUTPUT TRISTATE ;
    USE SIGNAL ;
    PORT
      LAYER met3 ;
        RECT 469.390 0.000 469.690 4.000 ;
    END
  END la_data_out_o[61]
  PIN la_data_out_o[62]
    DIRECTION OUTPUT TRISTATE ;
    USE SIGNAL ;
    PORT
      LAYER met3 ;
        RECT 476.870 0.000 477.170 4.000 ;
    END
  END la_data_out_o[62]
  PIN la_data_out_o[63]
    DIRECTION OUTPUT TRISTATE ;
    USE SIGNAL ;
    PORT
      LAYER met3 ;
        RECT 484.350 0.000 484.650 4.000 ;
    END
  END la_data_out_o[63]
  PIN la_data_out_o[64]
    DIRECTION OUTPUT TRISTATE ;
    USE SIGNAL ;
    PORT
      LAYER met3 ;
        RECT 491.830 0.000 492.130 4.000 ;
    END
  END la_data_out_o[64]
  PIN la_data_out_o[65]
    DIRECTION OUTPUT TRISTATE ;
    USE SIGNAL ;
    PORT
      LAYER met3 ;
        RECT 499.310 0.000 499.610 4.000 ;
    END
  END la_data_out_o[65]
  PIN la_data_out_o[66]
    DIRECTION OUTPUT TRISTATE ;
    USE SIGNAL ;
    PORT
      LAYER met3 ;
        RECT 506.790 0.000 507.090 4.000 ;
    END
  END la_data_out_o[66]
  PIN la_data_out_o[67]
    DIRECTION OUTPUT TRISTATE ;
    USE SIGNAL ;
    PORT
      LAYER met3 ;
        RECT 514.270 0.000 514.570 4.000 ;
    END
  END la_data_out_o[67]
  PIN la_data_out_o[68]
    DIRECTION OUTPUT TRISTATE ;
    USE SIGNAL ;
    PORT
      LAYER met3 ;
        RECT 521.750 0.000 522.050 4.000 ;
    END
  END la_data_out_o[68]
  PIN la_data_out_o[69]
    DIRECTION OUTPUT TRISTATE ;
    USE SIGNAL ;
    PORT
      LAYER met3 ;
        RECT 529.230 0.000 529.530 4.000 ;
    END
  END la_data_out_o[69]
  PIN la_data_out_o[6]
    DIRECTION OUTPUT TRISTATE ;
    USE SIGNAL ;
    PORT
      LAYER met3 ;
        RECT 57.990 0.000 58.290 4.000 ;
    END
  END la_data_out_o[6]
  PIN la_data_out_o[70]
    DIRECTION OUTPUT TRISTATE ;
    USE SIGNAL ;
    PORT
      LAYER met3 ;
        RECT 536.710 0.000 537.010 4.000 ;
    END
  END la_data_out_o[70]
  PIN la_data_out_o[71]
    DIRECTION OUTPUT TRISTATE ;
    USE SIGNAL ;
    PORT
      LAYER met3 ;
        RECT 544.190 0.000 544.490 4.000 ;
    END
  END la_data_out_o[71]
  PIN la_data_out_o[72]
    DIRECTION OUTPUT TRISTATE ;
    USE SIGNAL ;
    PORT
      LAYER met3 ;
        RECT 551.670 0.000 551.970 4.000 ;
    END
  END la_data_out_o[72]
  PIN la_data_out_o[73]
    DIRECTION OUTPUT TRISTATE ;
    USE SIGNAL ;
    PORT
      LAYER met3 ;
        RECT 559.150 0.000 559.450 4.000 ;
    END
  END la_data_out_o[73]
  PIN la_data_out_o[74]
    DIRECTION OUTPUT TRISTATE ;
    USE SIGNAL ;
    PORT
      LAYER met3 ;
        RECT 566.630 0.000 566.930 4.000 ;
    END
  END la_data_out_o[74]
  PIN la_data_out_o[75]
    DIRECTION OUTPUT TRISTATE ;
    USE SIGNAL ;
    PORT
      LAYER met3 ;
        RECT 574.110 0.000 574.410 4.000 ;
    END
  END la_data_out_o[75]
  PIN la_data_out_o[76]
    DIRECTION OUTPUT TRISTATE ;
    USE SIGNAL ;
    PORT
      LAYER met3 ;
        RECT 581.590 0.000 581.890 4.000 ;
    END
  END la_data_out_o[76]
  PIN la_data_out_o[77]
    DIRECTION OUTPUT TRISTATE ;
    USE SIGNAL ;
    PORT
      LAYER met3 ;
        RECT 589.070 0.000 589.370 4.000 ;
    END
  END la_data_out_o[77]
  PIN la_data_out_o[78]
    DIRECTION OUTPUT TRISTATE ;
    USE SIGNAL ;
    PORT
      LAYER met3 ;
        RECT 596.550 0.000 596.850 4.000 ;
    END
  END la_data_out_o[78]
  PIN la_data_out_o[79]
    DIRECTION OUTPUT TRISTATE ;
    USE SIGNAL ;
    PORT
      LAYER met3 ;
        RECT 604.030 0.000 604.330 4.000 ;
    END
  END la_data_out_o[79]
  PIN la_data_out_o[7]
    DIRECTION OUTPUT TRISTATE ;
    USE SIGNAL ;
    PORT
      LAYER met3 ;
        RECT 65.470 0.000 65.770 4.000 ;
    END
  END la_data_out_o[7]
  PIN la_data_out_o[80]
    DIRECTION OUTPUT TRISTATE ;
    USE SIGNAL ;
    PORT
      LAYER met3 ;
        RECT 611.510 0.000 611.810 4.000 ;
    END
  END la_data_out_o[80]
  PIN la_data_out_o[81]
    DIRECTION OUTPUT TRISTATE ;
    USE SIGNAL ;
    PORT
      LAYER met3 ;
        RECT 618.990 0.000 619.290 4.000 ;
    END
  END la_data_out_o[81]
  PIN la_data_out_o[82]
    DIRECTION OUTPUT TRISTATE ;
    USE SIGNAL ;
    PORT
      LAYER met3 ;
        RECT 626.470 0.000 626.770 4.000 ;
    END
  END la_data_out_o[82]
  PIN la_data_out_o[83]
    DIRECTION OUTPUT TRISTATE ;
    USE SIGNAL ;
    PORT
      LAYER met3 ;
        RECT 633.950 0.000 634.250 4.000 ;
    END
  END la_data_out_o[83]
  PIN la_data_out_o[84]
    DIRECTION OUTPUT TRISTATE ;
    USE SIGNAL ;
    PORT
      LAYER met3 ;
        RECT 641.430 0.000 641.730 4.000 ;
    END
  END la_data_out_o[84]
  PIN la_data_out_o[85]
    DIRECTION OUTPUT TRISTATE ;
    USE SIGNAL ;
    PORT
      LAYER met3 ;
        RECT 648.910 0.000 649.210 4.000 ;
    END
  END la_data_out_o[85]
  PIN la_data_out_o[86]
    DIRECTION OUTPUT TRISTATE ;
    USE SIGNAL ;
    PORT
      LAYER met3 ;
        RECT 656.390 0.000 656.690 4.000 ;
    END
  END la_data_out_o[86]
  PIN la_data_out_o[87]
    DIRECTION OUTPUT TRISTATE ;
    USE SIGNAL ;
    PORT
      LAYER met3 ;
        RECT 663.870 0.000 664.170 4.000 ;
    END
  END la_data_out_o[87]
  PIN la_data_out_o[88]
    DIRECTION OUTPUT TRISTATE ;
    USE SIGNAL ;
    PORT
      LAYER met3 ;
        RECT 671.350 0.000 671.650 4.000 ;
    END
  END la_data_out_o[88]
  PIN la_data_out_o[89]
    DIRECTION OUTPUT TRISTATE ;
    USE SIGNAL ;
    PORT
      LAYER met3 ;
        RECT 678.830 0.000 679.130 4.000 ;
    END
  END la_data_out_o[89]
  PIN la_data_out_o[8]
    DIRECTION OUTPUT TRISTATE ;
    USE SIGNAL ;
    PORT
      LAYER met3 ;
        RECT 72.950 0.000 73.250 4.000 ;
    END
  END la_data_out_o[8]
  PIN la_data_out_o[90]
    DIRECTION OUTPUT TRISTATE ;
    USE SIGNAL ;
    PORT
      LAYER met3 ;
        RECT 686.310 0.000 686.610 4.000 ;
    END
  END la_data_out_o[90]
  PIN la_data_out_o[91]
    DIRECTION OUTPUT TRISTATE ;
    USE SIGNAL ;
    PORT
      LAYER met3 ;
        RECT 693.790 0.000 694.090 4.000 ;
    END
  END la_data_out_o[91]
  PIN la_data_out_o[92]
    DIRECTION OUTPUT TRISTATE ;
    USE SIGNAL ;
    PORT
      LAYER met3 ;
        RECT 701.270 0.000 701.570 4.000 ;
    END
  END la_data_out_o[92]
  PIN la_data_out_o[93]
    DIRECTION OUTPUT TRISTATE ;
    USE SIGNAL ;
    PORT
      LAYER met3 ;
        RECT 708.750 0.000 709.050 4.000 ;
    END
  END la_data_out_o[93]
  PIN la_data_out_o[94]
    DIRECTION OUTPUT TRISTATE ;
    USE SIGNAL ;
    PORT
      LAYER met3 ;
        RECT 716.230 0.000 716.530 4.000 ;
    END
  END la_data_out_o[94]
  PIN la_data_out_o[95]
    DIRECTION OUTPUT TRISTATE ;
    USE SIGNAL ;
    PORT
      LAYER met3 ;
        RECT 723.710 0.000 724.010 4.000 ;
    END
  END la_data_out_o[95]
  PIN la_data_out_o[96]
    DIRECTION OUTPUT TRISTATE ;
    USE SIGNAL ;
    PORT
      LAYER met3 ;
        RECT 731.190 0.000 731.490 4.000 ;
    END
  END la_data_out_o[96]
  PIN la_data_out_o[97]
    DIRECTION OUTPUT TRISTATE ;
    USE SIGNAL ;
    PORT
      LAYER met3 ;
        RECT 738.670 0.000 738.970 4.000 ;
    END
  END la_data_out_o[97]
  PIN la_data_out_o[98]
    DIRECTION OUTPUT TRISTATE ;
    USE SIGNAL ;
    PORT
      LAYER met3 ;
        RECT 746.150 0.000 746.450 4.000 ;
    END
  END la_data_out_o[98]
  PIN la_data_out_o[99]
    DIRECTION OUTPUT TRISTATE ;
    USE SIGNAL ;
    PORT
      LAYER met3 ;
        RECT 753.630 0.000 753.930 4.000 ;
    END
  END la_data_out_o[99]
  PIN la_data_out_o[9]
    DIRECTION OUTPUT TRISTATE ;
    USE SIGNAL ;
    PORT
      LAYER met3 ;
        RECT 80.430 0.000 80.730 4.000 ;
    END
  END la_data_out_o[9]
  PIN mac_init_o
    DIRECTION OUTPUT TRISTATE ;
    USE SIGNAL ;
    ANTENNADIFFAREA 3.180800 ;
    PORT
      LAYER met3 ;
        RECT 152.510 796.000 152.810 800.000 ;
    END
  END mac_init_o
  PIN mem_addr_o[0]
    DIRECTION OUTPUT TRISTATE ;
    USE SIGNAL ;
    ANTENNADIFFAREA 3.180800 ;
    PORT
      LAYER met3 ;
        RECT 213.710 796.000 214.010 800.000 ;
    END
  END mem_addr_o[0]
  PIN mem_addr_o[1]
    DIRECTION OUTPUT TRISTATE ;
    USE SIGNAL ;
    ANTENNADIFFAREA 3.180800 ;
    PORT
      LAYER met3 ;
        RECT 223.910 796.000 224.210 800.000 ;
    END
  END mem_addr_o[1]
  PIN mem_addr_o[2]
    DIRECTION OUTPUT TRISTATE ;
    USE SIGNAL ;
    ANTENNADIFFAREA 3.180800 ;
    PORT
      LAYER met3 ;
        RECT 234.110 796.000 234.410 800.000 ;
    END
  END mem_addr_o[2]
  PIN mem_addr_o[3]
    DIRECTION OUTPUT TRISTATE ;
    USE SIGNAL ;
    ANTENNADIFFAREA 3.180800 ;
    PORT
      LAYER met3 ;
        RECT 244.310 796.000 244.610 800.000 ;
    END
  END mem_addr_o[3]
  PIN mem_addr_o[4]
    DIRECTION OUTPUT TRISTATE ;
    USE SIGNAL ;
    ANTENNADIFFAREA 3.180800 ;
    PORT
      LAYER met3 ;
        RECT 254.510 796.000 254.810 800.000 ;
    END
  END mem_addr_o[4]
  PIN mem_addr_o[5]
    DIRECTION OUTPUT TRISTATE ;
    USE SIGNAL ;
    ANTENNADIFFAREA 3.180800 ;
    PORT
      LAYER met3 ;
        RECT 264.710 796.000 265.010 800.000 ;
    END
  END mem_addr_o[5]
  PIN mem_addr_o[6]
    DIRECTION OUTPUT TRISTATE ;
    USE SIGNAL ;
    ANTENNADIFFAREA 3.180800 ;
    PORT
      LAYER met3 ;
        RECT 274.910 796.000 275.210 800.000 ;
    END
  END mem_addr_o[6]
  PIN mem_addr_o[7]
    DIRECTION OUTPUT TRISTATE ;
    USE SIGNAL ;
    ANTENNADIFFAREA 3.180800 ;
    PORT
      LAYER met3 ;
        RECT 285.110 796.000 285.410 800.000 ;
    END
  END mem_addr_o[7]
  PIN mem_addr_o[8]
    DIRECTION OUTPUT TRISTATE ;
    USE SIGNAL ;
    ANTENNADIFFAREA 3.180800 ;
    PORT
      LAYER met3 ;
        RECT 295.310 796.000 295.610 800.000 ;
    END
  END mem_addr_o[8]
  PIN mem_rdata_i[0]
    DIRECTION INPUT ;
    USE SIGNAL ;
    ANTENNAGATEAREA 0.196500 ;
    ANTENNADIFFAREA 0.434700 ;
    PORT
      LAYER met3 ;
        RECT 631.910 796.000 632.210 800.000 ;
    END
  END mem_rdata_i[0]
  PIN mem_rdata_i[10]
    DIRECTION INPUT ;
    USE SIGNAL ;
    ANTENNAGATEAREA 0.196500 ;
    ANTENNADIFFAREA 0.434700 ;
    PORT
      LAYER met3 ;
        RECT 733.910 796.000 734.210 800.000 ;
    END
  END mem_rdata_i[10]
  PIN mem_rdata_i[11]
    DIRECTION INPUT ;
    USE SIGNAL ;
    ANTENNAGATEAREA 0.196500 ;
    ANTENNADIFFAREA 0.434700 ;
    PORT
      LAYER met3 ;
        RECT 744.110 796.000 744.410 800.000 ;
    END
  END mem_rdata_i[11]
  PIN mem_rdata_i[12]
    DIRECTION INPUT ;
    USE SIGNAL ;
    ANTENNAGATEAREA 0.196500 ;
    ANTENNADIFFAREA 0.434700 ;
    PORT
      LAYER met3 ;
        RECT 754.310 796.000 754.610 800.000 ;
    END
  END mem_rdata_i[12]
  PIN mem_rdata_i[13]
    DIRECTION INPUT ;
    USE SIGNAL ;
    ANTENNAGATEAREA 0.196500 ;
    ANTENNADIFFAREA 0.434700 ;
    PORT
      LAYER met3 ;
        RECT 764.510 796.000 764.810 800.000 ;
    END
  END mem_rdata_i[13]
  PIN mem_rdata_i[14]
    DIRECTION INPUT ;
    USE SIGNAL ;
    ANTENNAGATEAREA 0.196500 ;
    ANTENNADIFFAREA 0.434700 ;
    PORT
      LAYER met3 ;
        RECT 774.710 796.000 775.010 800.000 ;
    END
  END mem_rdata_i[14]
  PIN mem_rdata_i[15]
    DIRECTION INPUT ;
    USE SIGNAL ;
    ANTENNAGATEAREA 0.196500 ;
    ANTENNADIFFAREA 0.434700 ;
    PORT
      LAYER met3 ;
        RECT 784.910 796.000 785.210 800.000 ;
    END
  END mem_rdata_i[15]
  PIN mem_rdata_i[16]
    DIRECTION INPUT ;
    USE SIGNAL ;
    ANTENNAGATEAREA 0.196500 ;
    ANTENNADIFFAREA 0.434700 ;
    PORT
      LAYER met3 ;
        RECT 795.110 796.000 795.410 800.000 ;
    END
  END mem_rdata_i[16]
  PIN mem_rdata_i[17]
    DIRECTION INPUT ;
    USE SIGNAL ;
    ANTENNAGATEAREA 0.196500 ;
    ANTENNADIFFAREA 0.434700 ;
    PORT
      LAYER met3 ;
        RECT 805.310 796.000 805.610 800.000 ;
    END
  END mem_rdata_i[17]
  PIN mem_rdata_i[18]
    DIRECTION INPUT ;
    USE SIGNAL ;
    ANTENNAGATEAREA 0.196500 ;
    ANTENNADIFFAREA 0.434700 ;
    PORT
      LAYER met3 ;
        RECT 815.510 796.000 815.810 800.000 ;
    END
  END mem_rdata_i[18]
  PIN mem_rdata_i[19]
    DIRECTION INPUT ;
    USE SIGNAL ;
    ANTENNAGATEAREA 0.196500 ;
    ANTENNADIFFAREA 0.434700 ;
    PORT
      LAYER met3 ;
        RECT 825.710 796.000 826.010 800.000 ;
    END
  END mem_rdata_i[19]
  PIN mem_rdata_i[1]
    DIRECTION INPUT ;
    USE SIGNAL ;
    ANTENNAGATEAREA 0.196500 ;
    ANTENNADIFFAREA 0.434700 ;
    PORT
      LAYER met3 ;
        RECT 642.110 796.000 642.410 800.000 ;
    END
  END mem_rdata_i[1]
  PIN mem_rdata_i[20]
    DIRECTION INPUT ;
    USE SIGNAL ;
    ANTENNAGATEAREA 0.196500 ;
    ANTENNADIFFAREA 0.434700 ;
    PORT
      LAYER met3 ;
        RECT 835.910 796.000 836.210 800.000 ;
    END
  END mem_rdata_i[20]
  PIN mem_rdata_i[21]
    DIRECTION INPUT ;
    USE SIGNAL ;
    ANTENNAGATEAREA 0.196500 ;
    ANTENNADIFFAREA 0.434700 ;
    PORT
      LAYER met3 ;
        RECT 846.110 796.000 846.410 800.000 ;
    END
  END mem_rdata_i[21]
  PIN mem_rdata_i[22]
    DIRECTION INPUT ;
    USE SIGNAL ;
    ANTENNAGATEAREA 0.196500 ;
    ANTENNADIFFAREA 0.434700 ;
    PORT
      LAYER met3 ;
        RECT 856.310 796.000 856.610 800.000 ;
    END
  END mem_rdata_i[22]
  PIN mem_rdata_i[23]
    DIRECTION INPUT ;
    USE SIGNAL ;
    ANTENNAGATEAREA 0.196500 ;
    ANTENNADIFFAREA 0.434700 ;
    PORT
      LAYER met3 ;
        RECT 866.510 796.000 866.810 800.000 ;
    END
  END mem_rdata_i[23]
  PIN mem_rdata_i[24]
    DIRECTION INPUT ;
    USE SIGNAL ;
    ANTENNAGATEAREA 0.196500 ;
    ANTENNADIFFAREA 0.434700 ;
    PORT
      LAYER met3 ;
        RECT 876.710 796.000 877.010 800.000 ;
    END
  END mem_rdata_i[24]
  PIN mem_rdata_i[25]
    DIRECTION INPUT ;
    USE SIGNAL ;
    ANTENNAGATEAREA 0.196500 ;
    ANTENNADIFFAREA 0.434700 ;
    PORT
      LAYER met3 ;
        RECT 886.910 796.000 887.210 800.000 ;
    END
  END mem_rdata_i[25]
  PIN mem_rdata_i[26]
    DIRECTION INPUT ;
    USE SIGNAL ;
    ANTENNAGATEAREA 0.196500 ;
    ANTENNADIFFAREA 0.434700 ;
    PORT
      LAYER met3 ;
        RECT 897.110 796.000 897.410 800.000 ;
    END
  END mem_rdata_i[26]
  PIN mem_rdata_i[27]
    DIRECTION INPUT ;
    USE SIGNAL ;
    ANTENNAGATEAREA 0.196500 ;
    ANTENNADIFFAREA 0.434700 ;
    PORT
      LAYER met3 ;
        RECT 907.310 796.000 907.610 800.000 ;
    END
  END mem_rdata_i[27]
  PIN mem_rdata_i[28]
    DIRECTION INPUT ;
    USE SIGNAL ;
    ANTENNAGATEAREA 0.196500 ;
    ANTENNADIFFAREA 0.434700 ;
    PORT
      LAYER met3 ;
        RECT 917.510 796.000 917.810 800.000 ;
    END
  END mem_rdata_i[28]
  PIN mem_rdata_i[29]
    DIRECTION INPUT ;
    USE SIGNAL ;
    ANTENNAGATEAREA 0.196500 ;
    ANTENNADIFFAREA 0.434700 ;
    PORT
      LAYER met3 ;
        RECT 927.710 796.000 928.010 800.000 ;
    END
  END mem_rdata_i[29]
  PIN mem_rdata_i[2]
    DIRECTION INPUT ;
    USE SIGNAL ;
    ANTENNAGATEAREA 0.196500 ;
    ANTENNADIFFAREA 0.434700 ;
    PORT
      LAYER met3 ;
        RECT 652.310 796.000 652.610 800.000 ;
    END
  END mem_rdata_i[2]
  PIN mem_rdata_i[30]
    DIRECTION INPUT ;
    USE SIGNAL ;
    ANTENNAGATEAREA 0.196500 ;
    ANTENNADIFFAREA 0.434700 ;
    PORT
      LAYER met3 ;
        RECT 937.910 796.000 938.210 800.000 ;
    END
  END mem_rdata_i[30]
  PIN mem_rdata_i[31]
    DIRECTION INPUT ;
    USE SIGNAL ;
    ANTENNAGATEAREA 0.196500 ;
    ANTENNADIFFAREA 0.434700 ;
    PORT
      LAYER met3 ;
        RECT 948.110 796.000 948.410 800.000 ;
    END
  END mem_rdata_i[31]
  PIN mem_rdata_i[3]
    DIRECTION INPUT ;
    USE SIGNAL ;
    ANTENNAGATEAREA 0.196500 ;
    ANTENNADIFFAREA 0.434700 ;
    PORT
      LAYER met3 ;
        RECT 662.510 796.000 662.810 800.000 ;
    END
  END mem_rdata_i[3]
  PIN mem_rdata_i[4]
    DIRECTION INPUT ;
    USE SIGNAL ;
    ANTENNAGATEAREA 0.196500 ;
    ANTENNADIFFAREA 0.434700 ;
    PORT
      LAYER met3 ;
        RECT 672.710 796.000 673.010 800.000 ;
    END
  END mem_rdata_i[4]
  PIN mem_rdata_i[5]
    DIRECTION INPUT ;
    USE SIGNAL ;
    ANTENNAGATEAREA 0.196500 ;
    ANTENNADIFFAREA 0.434700 ;
    PORT
      LAYER met3 ;
        RECT 682.910 796.000 683.210 800.000 ;
    END
  END mem_rdata_i[5]
  PIN mem_rdata_i[6]
    DIRECTION INPUT ;
    USE SIGNAL ;
    ANTENNAGATEAREA 0.196500 ;
    ANTENNADIFFAREA 0.434700 ;
    PORT
      LAYER met3 ;
        RECT 693.110 796.000 693.410 800.000 ;
    END
  END mem_rdata_i[6]
  PIN mem_rdata_i[7]
    DIRECTION INPUT ;
    USE SIGNAL ;
    ANTENNAGATEAREA 0.196500 ;
    ANTENNADIFFAREA 0.434700 ;
    PORT
      LAYER met3 ;
        RECT 703.310 796.000 703.610 800.000 ;
    END
  END mem_rdata_i[7]
  PIN mem_rdata_i[8]
    DIRECTION INPUT ;
    USE SIGNAL ;
    ANTENNAGATEAREA 0.196500 ;
    ANTENNADIFFAREA 0.434700 ;
    PORT
      LAYER met3 ;
        RECT 713.510 796.000 713.810 800.000 ;
    END
  END mem_rdata_i[8]
  PIN mem_rdata_i[9]
    DIRECTION INPUT ;
    USE SIGNAL ;
    ANTENNAGATEAREA 0.196500 ;
    ANTENNADIFFAREA 0.434700 ;
    PORT
      LAYER met3 ;
        RECT 723.710 796.000 724.010 800.000 ;
    END
  END mem_rdata_i[9]
  PIN mem_re_o
    DIRECTION OUTPUT TRISTATE ;
    USE SIGNAL ;
    ANTENNADIFFAREA 3.180800 ;
    PORT
      LAYER met3 ;
        RECT 172.910 796.000 173.210 800.000 ;
    END
  END mem_re_o
  PIN mem_rvalid_i
    DIRECTION INPUT ;
    USE SIGNAL ;
    ANTENNAGATEAREA 0.196500 ;
    ANTENNADIFFAREA 0.434700 ;
    PORT
      LAYER met3 ;
        RECT 958.310 796.000 958.610 800.000 ;
    END
  END mem_rvalid_i
  PIN mem_slot_o[0]
    DIRECTION OUTPUT TRISTATE ;
    USE SIGNAL ;
    ANTENNADIFFAREA 3.180800 ;
    PORT
      LAYER met3 ;
        RECT 193.310 796.000 193.610 800.000 ;
    END
  END mem_slot_o[0]
  PIN mem_slot_o[1]
    DIRECTION OUTPUT TRISTATE ;
    USE SIGNAL ;
    ANTENNADIFFAREA 3.180800 ;
    PORT
      LAYER met3 ;
        RECT 203.510 796.000 203.810 800.000 ;
    END
  END mem_slot_o[1]
  PIN mem_target_o
    DIRECTION OUTPUT TRISTATE ;
    USE SIGNAL ;
    ANTENNADIFFAREA 3.180800 ;
    PORT
      LAYER met3 ;
        RECT 183.110 796.000 183.410 800.000 ;
    END
  END mem_target_o
  PIN mem_wdata_o[0]
    DIRECTION OUTPUT TRISTATE ;
    USE SIGNAL ;
    ANTENNADIFFAREA 3.180800 ;
    PORT
      LAYER met3 ;
        RECT 305.510 796.000 305.810 800.000 ;
    END
  END mem_wdata_o[0]
  PIN mem_wdata_o[10]
    DIRECTION OUTPUT TRISTATE ;
    USE SIGNAL ;
    ANTENNADIFFAREA 3.180800 ;
    PORT
      LAYER met3 ;
        RECT 407.510 796.000 407.810 800.000 ;
    END
  END mem_wdata_o[10]
  PIN mem_wdata_o[11]
    DIRECTION OUTPUT TRISTATE ;
    USE SIGNAL ;
    ANTENNADIFFAREA 3.180800 ;
    PORT
      LAYER met3 ;
        RECT 417.710 796.000 418.010 800.000 ;
    END
  END mem_wdata_o[11]
  PIN mem_wdata_o[12]
    DIRECTION OUTPUT TRISTATE ;
    USE SIGNAL ;
    ANTENNADIFFAREA 3.180800 ;
    PORT
      LAYER met3 ;
        RECT 427.910 796.000 428.210 800.000 ;
    END
  END mem_wdata_o[12]
  PIN mem_wdata_o[13]
    DIRECTION OUTPUT TRISTATE ;
    USE SIGNAL ;
    ANTENNADIFFAREA 3.180800 ;
    PORT
      LAYER met3 ;
        RECT 438.110 796.000 438.410 800.000 ;
    END
  END mem_wdata_o[13]
  PIN mem_wdata_o[14]
    DIRECTION OUTPUT TRISTATE ;
    USE SIGNAL ;
    ANTENNADIFFAREA 3.180800 ;
    PORT
      LAYER met3 ;
        RECT 448.310 796.000 448.610 800.000 ;
    END
  END mem_wdata_o[14]
  PIN mem_wdata_o[15]
    DIRECTION OUTPUT TRISTATE ;
    USE SIGNAL ;
    ANTENNADIFFAREA 3.180800 ;
    PORT
      LAYER met3 ;
        RECT 458.510 796.000 458.810 800.000 ;
    END
  END mem_wdata_o[15]
  PIN mem_wdata_o[16]
    DIRECTION OUTPUT TRISTATE ;
    USE SIGNAL ;
    ANTENNADIFFAREA 3.180800 ;
    PORT
      LAYER met3 ;
        RECT 468.710 796.000 469.010 800.000 ;
    END
  END mem_wdata_o[16]
  PIN mem_wdata_o[17]
    DIRECTION OUTPUT TRISTATE ;
    USE SIGNAL ;
    ANTENNADIFFAREA 3.180800 ;
    PORT
      LAYER met3 ;
        RECT 478.910 796.000 479.210 800.000 ;
    END
  END mem_wdata_o[17]
  PIN mem_wdata_o[18]
    DIRECTION OUTPUT TRISTATE ;
    USE SIGNAL ;
    ANTENNADIFFAREA 3.180800 ;
    PORT
      LAYER met3 ;
        RECT 489.110 796.000 489.410 800.000 ;
    END
  END mem_wdata_o[18]
  PIN mem_wdata_o[19]
    DIRECTION OUTPUT TRISTATE ;
    USE SIGNAL ;
    ANTENNADIFFAREA 3.180800 ;
    PORT
      LAYER met3 ;
        RECT 499.310 796.000 499.610 800.000 ;
    END
  END mem_wdata_o[19]
  PIN mem_wdata_o[1]
    DIRECTION OUTPUT TRISTATE ;
    USE SIGNAL ;
    ANTENNADIFFAREA 3.180800 ;
    PORT
      LAYER met3 ;
        RECT 315.710 796.000 316.010 800.000 ;
    END
  END mem_wdata_o[1]
  PIN mem_wdata_o[20]
    DIRECTION OUTPUT TRISTATE ;
    USE SIGNAL ;
    ANTENNADIFFAREA 3.180800 ;
    PORT
      LAYER met3 ;
        RECT 509.510 796.000 509.810 800.000 ;
    END
  END mem_wdata_o[20]
  PIN mem_wdata_o[21]
    DIRECTION OUTPUT TRISTATE ;
    USE SIGNAL ;
    ANTENNADIFFAREA 3.180800 ;
    PORT
      LAYER met3 ;
        RECT 519.710 796.000 520.010 800.000 ;
    END
  END mem_wdata_o[21]
  PIN mem_wdata_o[22]
    DIRECTION OUTPUT TRISTATE ;
    USE SIGNAL ;
    ANTENNADIFFAREA 3.180800 ;
    PORT
      LAYER met3 ;
        RECT 529.910 796.000 530.210 800.000 ;
    END
  END mem_wdata_o[22]
  PIN mem_wdata_o[23]
    DIRECTION OUTPUT TRISTATE ;
    USE SIGNAL ;
    ANTENNADIFFAREA 3.180800 ;
    PORT
      LAYER met3 ;
        RECT 540.110 796.000 540.410 800.000 ;
    END
  END mem_wdata_o[23]
  PIN mem_wdata_o[24]
    DIRECTION OUTPUT TRISTATE ;
    USE SIGNAL ;
    ANTENNADIFFAREA 3.180800 ;
    PORT
      LAYER met3 ;
        RECT 550.310 796.000 550.610 800.000 ;
    END
  END mem_wdata_o[24]
  PIN mem_wdata_o[25]
    DIRECTION OUTPUT TRISTATE ;
    USE SIGNAL ;
    ANTENNADIFFAREA 3.180800 ;
    PORT
      LAYER met3 ;
        RECT 560.510 796.000 560.810 800.000 ;
    END
  END mem_wdata_o[25]
  PIN mem_wdata_o[26]
    DIRECTION OUTPUT TRISTATE ;
    USE SIGNAL ;
    ANTENNADIFFAREA 3.180800 ;
    PORT
      LAYER met3 ;
        RECT 570.710 796.000 571.010 800.000 ;
    END
  END mem_wdata_o[26]
  PIN mem_wdata_o[27]
    DIRECTION OUTPUT TRISTATE ;
    USE SIGNAL ;
    ANTENNADIFFAREA 3.180800 ;
    PORT
      LAYER met3 ;
        RECT 580.910 796.000 581.210 800.000 ;
    END
  END mem_wdata_o[27]
  PIN mem_wdata_o[28]
    DIRECTION OUTPUT TRISTATE ;
    USE SIGNAL ;
    ANTENNADIFFAREA 3.180800 ;
    PORT
      LAYER met3 ;
        RECT 591.110 796.000 591.410 800.000 ;
    END
  END mem_wdata_o[28]
  PIN mem_wdata_o[29]
    DIRECTION OUTPUT TRISTATE ;
    USE SIGNAL ;
    ANTENNADIFFAREA 3.180800 ;
    PORT
      LAYER met3 ;
        RECT 601.310 796.000 601.610 800.000 ;
    END
  END mem_wdata_o[29]
  PIN mem_wdata_o[2]
    DIRECTION OUTPUT TRISTATE ;
    USE SIGNAL ;
    ANTENNADIFFAREA 3.180800 ;
    PORT
      LAYER met3 ;
        RECT 325.910 796.000 326.210 800.000 ;
    END
  END mem_wdata_o[2]
  PIN mem_wdata_o[30]
    DIRECTION OUTPUT TRISTATE ;
    USE SIGNAL ;
    ANTENNADIFFAREA 3.180800 ;
    PORT
      LAYER met3 ;
        RECT 611.510 796.000 611.810 800.000 ;
    END
  END mem_wdata_o[30]
  PIN mem_wdata_o[31]
    DIRECTION OUTPUT TRISTATE ;
    USE SIGNAL ;
    ANTENNADIFFAREA 3.180800 ;
    PORT
      LAYER met3 ;
        RECT 621.710 796.000 622.010 800.000 ;
    END
  END mem_wdata_o[31]
  PIN mem_wdata_o[3]
    DIRECTION OUTPUT TRISTATE ;
    USE SIGNAL ;
    ANTENNADIFFAREA 3.180800 ;
    PORT
      LAYER met3 ;
        RECT 336.110 796.000 336.410 800.000 ;
    END
  END mem_wdata_o[3]
  PIN mem_wdata_o[4]
    DIRECTION OUTPUT TRISTATE ;
    USE SIGNAL ;
    ANTENNADIFFAREA 3.180800 ;
    PORT
      LAYER met3 ;
        RECT 346.310 796.000 346.610 800.000 ;
    END
  END mem_wdata_o[4]
  PIN mem_wdata_o[5]
    DIRECTION OUTPUT TRISTATE ;
    USE SIGNAL ;
    ANTENNADIFFAREA 3.180800 ;
    PORT
      LAYER met3 ;
        RECT 356.510 796.000 356.810 800.000 ;
    END
  END mem_wdata_o[5]
  PIN mem_wdata_o[6]
    DIRECTION OUTPUT TRISTATE ;
    USE SIGNAL ;
    ANTENNADIFFAREA 3.180800 ;
    PORT
      LAYER met3 ;
        RECT 366.710 796.000 367.010 800.000 ;
    END
  END mem_wdata_o[6]
  PIN mem_wdata_o[7]
    DIRECTION OUTPUT TRISTATE ;
    USE SIGNAL ;
    ANTENNADIFFAREA 3.180800 ;
    PORT
      LAYER met3 ;
        RECT 376.910 796.000 377.210 800.000 ;
    END
  END mem_wdata_o[7]
  PIN mem_wdata_o[8]
    DIRECTION OUTPUT TRISTATE ;
    USE SIGNAL ;
    ANTENNADIFFAREA 3.180800 ;
    PORT
      LAYER met3 ;
        RECT 387.110 796.000 387.410 800.000 ;
    END
  END mem_wdata_o[8]
  PIN mem_wdata_o[9]
    DIRECTION OUTPUT TRISTATE ;
    USE SIGNAL ;
    ANTENNADIFFAREA 3.180800 ;
    PORT
      LAYER met3 ;
        RECT 397.310 796.000 397.610 800.000 ;
    END
  END mem_wdata_o[9]
  PIN mem_we_o
    DIRECTION OUTPUT TRISTATE ;
    USE SIGNAL ;
    ANTENNADIFFAREA 3.180800 ;
    PORT
      LAYER met3 ;
        RECT 162.710 796.000 163.010 800.000 ;
    END
  END mem_we_o
  PIN op_o[0]
    DIRECTION OUTPUT TRISTATE ;
    USE SIGNAL ;
    ANTENNADIFFAREA 3.180800 ;
    PORT
      LAYER met3 ;
        RECT 60.710 796.000 61.010 800.000 ;
    END
  END op_o[0]
  PIN op_o[1]
    DIRECTION OUTPUT TRISTATE ;
    USE SIGNAL ;
    ANTENNADIFFAREA 3.180800 ;
    PORT
      LAYER met3 ;
        RECT 70.910 796.000 71.210 800.000 ;
    END
  END op_o[1]
  PIN op_o[2]
    DIRECTION OUTPUT TRISTATE ;
    USE SIGNAL ;
    ANTENNADIFFAREA 3.180800 ;
    PORT
      LAYER met3 ;
        RECT 81.110 796.000 81.410 800.000 ;
    END
  END op_o[2]
  PIN slot_a_o[0]
    DIRECTION OUTPUT TRISTATE ;
    USE SIGNAL ;
    ANTENNADIFFAREA 3.180800 ;
    PORT
      LAYER met3 ;
        RECT 91.310 796.000 91.610 800.000 ;
    END
  END slot_a_o[0]
  PIN slot_a_o[1]
    DIRECTION OUTPUT TRISTATE ;
    USE SIGNAL ;
    ANTENNADIFFAREA 3.180800 ;
    PORT
      LAYER met3 ;
        RECT 101.510 796.000 101.810 800.000 ;
    END
  END slot_a_o[1]
  PIN slot_b_o[0]
    DIRECTION OUTPUT TRISTATE ;
    USE SIGNAL ;
    ANTENNADIFFAREA 3.180800 ;
    PORT
      LAYER met3 ;
        RECT 111.710 796.000 112.010 800.000 ;
    END
  END slot_b_o[0]
  PIN slot_b_o[1]
    DIRECTION OUTPUT TRISTATE ;
    USE SIGNAL ;
    ANTENNADIFFAREA 3.180800 ;
    PORT
      LAYER met3 ;
        RECT 121.910 796.000 122.210 800.000 ;
    END
  END slot_b_o[1]
  PIN slot_c_o[0]
    DIRECTION OUTPUT TRISTATE ;
    USE SIGNAL ;
    ANTENNADIFFAREA 3.180800 ;
    PORT
      LAYER met3 ;
        RECT 132.110 796.000 132.410 800.000 ;
    END
  END slot_c_o[0]
  PIN slot_c_o[1]
    DIRECTION OUTPUT TRISTATE ;
    USE SIGNAL ;
    ANTENNADIFFAREA 3.180800 ;
    PORT
      LAYER met3 ;
        RECT 142.310 796.000 142.610 800.000 ;
    END
  END slot_c_o[1]
  PIN start_o
    DIRECTION OUTPUT TRISTATE ;
    USE SIGNAL ;
    ANTENNADIFFAREA 3.180800 ;
    PORT
      LAYER met3 ;
        RECT 40.310 796.000 40.610 800.000 ;
    END
  END start_o
  PIN user_irq_o[0]
    DIRECTION OUTPUT TRISTATE ;
    USE SIGNAL ;
    ANTENNADIFFAREA 3.180800 ;
    PORT
      LAYER met3 ;
        RECT 970.550 0.000 970.850 4.000 ;
    END
  END user_irq_o[0]
  PIN user_irq_o[1]
    DIRECTION OUTPUT TRISTATE ;
    USE SIGNAL ;
    ANTENNADIFFAREA 3.180800 ;
    PORT
      LAYER met3 ;
        RECT 978.030 0.000 978.330 4.000 ;
    END
  END user_irq_o[1]
  PIN user_irq_o[2]
    DIRECTION OUTPUT TRISTATE ;
    USE SIGNAL ;
    PORT
      LAYER met3 ;
        RECT 985.510 0.000 985.810 4.000 ;
    END
  END user_irq_o[2]
  PIN wb_clk_i
    DIRECTION INPUT ;
    USE SIGNAL ;
    ANTENNAGATEAREA 0.852000 ;
    ANTENNADIFFAREA 0.434700 ;
    PORT
      LAYER met3 ;
        RECT 0.000 36.760 4.000 37.360 ;
    END
  END wb_clk_i
  PIN wb_rst_i
    DIRECTION INPUT ;
    USE SIGNAL ;
    ANTENNAGATEAREA 0.196500 ;
    ANTENNADIFFAREA 0.434700 ;
    PORT
      LAYER met3 ;
        RECT 0.000 42.200 4.000 42.800 ;
    END
  END wb_rst_i
  PIN wbs_ack_o
    DIRECTION OUTPUT TRISTATE ;
    USE SIGNAL ;
    ANTENNADIFFAREA 3.180800 ;
    PORT
      LAYER met3 ;
        RECT 0.000 433.880 4.000 434.480 ;
    END
  END wbs_ack_o
  PIN wbs_adr_i[0]
    DIRECTION INPUT ;
    USE SIGNAL ;
    ANTENNAGATEAREA 0.196500 ;
    ANTENNADIFFAREA 0.434700 ;
    PORT
      LAYER met3 ;
        RECT 0.000 85.720 4.000 86.320 ;
    END
  END wbs_adr_i[0]
  PIN wbs_adr_i[10]
    DIRECTION INPUT ;
    USE SIGNAL ;
    PORT
      LAYER met3 ;
        RECT 0.000 140.120 4.000 140.720 ;
    END
  END wbs_adr_i[10]
  PIN wbs_adr_i[11]
    DIRECTION INPUT ;
    USE SIGNAL ;
    PORT
      LAYER met3 ;
        RECT 0.000 145.560 4.000 146.160 ;
    END
  END wbs_adr_i[11]
  PIN wbs_adr_i[12]
    DIRECTION INPUT ;
    USE SIGNAL ;
    PORT
      LAYER met3 ;
        RECT 0.000 151.000 4.000 151.600 ;
    END
  END wbs_adr_i[12]
  PIN wbs_adr_i[13]
    DIRECTION INPUT ;
    USE SIGNAL ;
    PORT
      LAYER met3 ;
        RECT 0.000 156.440 4.000 157.040 ;
    END
  END wbs_adr_i[13]
  PIN wbs_adr_i[14]
    DIRECTION INPUT ;
    USE SIGNAL ;
    PORT
      LAYER met3 ;
        RECT 0.000 161.880 4.000 162.480 ;
    END
  END wbs_adr_i[14]
  PIN wbs_adr_i[15]
    DIRECTION INPUT ;
    USE SIGNAL ;
    PORT
      LAYER met3 ;
        RECT 0.000 167.320 4.000 167.920 ;
    END
  END wbs_adr_i[15]
  PIN wbs_adr_i[16]
    DIRECTION INPUT ;
    USE SIGNAL ;
    PORT
      LAYER met3 ;
        RECT 0.000 172.760 4.000 173.360 ;
    END
  END wbs_adr_i[16]
  PIN wbs_adr_i[17]
    DIRECTION INPUT ;
    USE SIGNAL ;
    PORT
      LAYER met3 ;
        RECT 0.000 178.200 4.000 178.800 ;
    END
  END wbs_adr_i[17]
  PIN wbs_adr_i[18]
    DIRECTION INPUT ;
    USE SIGNAL ;
    PORT
      LAYER met3 ;
        RECT 0.000 183.640 4.000 184.240 ;
    END
  END wbs_adr_i[18]
  PIN wbs_adr_i[19]
    DIRECTION INPUT ;
    USE SIGNAL ;
    PORT
      LAYER met3 ;
        RECT 0.000 189.080 4.000 189.680 ;
    END
  END wbs_adr_i[19]
  PIN wbs_adr_i[1]
    DIRECTION INPUT ;
    USE SIGNAL ;
    ANTENNAGATEAREA 0.196500 ;
    ANTENNADIFFAREA 0.434700 ;
    PORT
      LAYER met3 ;
        RECT 0.000 91.160 4.000 91.760 ;
    END
  END wbs_adr_i[1]
  PIN wbs_adr_i[20]
    DIRECTION INPUT ;
    USE SIGNAL ;
    PORT
      LAYER met3 ;
        RECT 0.000 194.520 4.000 195.120 ;
    END
  END wbs_adr_i[20]
  PIN wbs_adr_i[21]
    DIRECTION INPUT ;
    USE SIGNAL ;
    PORT
      LAYER met3 ;
        RECT 0.000 199.960 4.000 200.560 ;
    END
  END wbs_adr_i[21]
  PIN wbs_adr_i[22]
    DIRECTION INPUT ;
    USE SIGNAL ;
    PORT
      LAYER met3 ;
        RECT 0.000 205.400 4.000 206.000 ;
    END
  END wbs_adr_i[22]
  PIN wbs_adr_i[23]
    DIRECTION INPUT ;
    USE SIGNAL ;
    PORT
      LAYER met3 ;
        RECT 0.000 210.840 4.000 211.440 ;
    END
  END wbs_adr_i[23]
  PIN wbs_adr_i[24]
    DIRECTION INPUT ;
    USE SIGNAL ;
    PORT
      LAYER met3 ;
        RECT 0.000 216.280 4.000 216.880 ;
    END
  END wbs_adr_i[24]
  PIN wbs_adr_i[25]
    DIRECTION INPUT ;
    USE SIGNAL ;
    PORT
      LAYER met3 ;
        RECT 0.000 221.720 4.000 222.320 ;
    END
  END wbs_adr_i[25]
  PIN wbs_adr_i[26]
    DIRECTION INPUT ;
    USE SIGNAL ;
    PORT
      LAYER met3 ;
        RECT 0.000 227.160 4.000 227.760 ;
    END
  END wbs_adr_i[26]
  PIN wbs_adr_i[27]
    DIRECTION INPUT ;
    USE SIGNAL ;
    PORT
      LAYER met3 ;
        RECT 0.000 232.600 4.000 233.200 ;
    END
  END wbs_adr_i[27]
  PIN wbs_adr_i[28]
    DIRECTION INPUT ;
    USE SIGNAL ;
    PORT
      LAYER met3 ;
        RECT 0.000 238.040 4.000 238.640 ;
    END
  END wbs_adr_i[28]
  PIN wbs_adr_i[29]
    DIRECTION INPUT ;
    USE SIGNAL ;
    PORT
      LAYER met3 ;
        RECT 0.000 243.480 4.000 244.080 ;
    END
  END wbs_adr_i[29]
  PIN wbs_adr_i[2]
    DIRECTION INPUT ;
    USE SIGNAL ;
    ANTENNAGATEAREA 0.196500 ;
    ANTENNADIFFAREA 0.434700 ;
    PORT
      LAYER met3 ;
        RECT 0.000 96.600 4.000 97.200 ;
    END
  END wbs_adr_i[2]
  PIN wbs_adr_i[30]
    DIRECTION INPUT ;
    USE SIGNAL ;
    PORT
      LAYER met3 ;
        RECT 0.000 248.920 4.000 249.520 ;
    END
  END wbs_adr_i[30]
  PIN wbs_adr_i[31]
    DIRECTION INPUT ;
    USE SIGNAL ;
    PORT
      LAYER met3 ;
        RECT 0.000 254.360 4.000 254.960 ;
    END
  END wbs_adr_i[31]
  PIN wbs_adr_i[3]
    DIRECTION INPUT ;
    USE SIGNAL ;
    ANTENNAGATEAREA 0.196500 ;
    ANTENNADIFFAREA 0.434700 ;
    PORT
      LAYER met3 ;
        RECT 0.000 102.040 4.000 102.640 ;
    END
  END wbs_adr_i[3]
  PIN wbs_adr_i[4]
    DIRECTION INPUT ;
    USE SIGNAL ;
    ANTENNAGATEAREA 0.196500 ;
    ANTENNADIFFAREA 0.434700 ;
    PORT
      LAYER met3 ;
        RECT 0.000 107.480 4.000 108.080 ;
    END
  END wbs_adr_i[4]
  PIN wbs_adr_i[5]
    DIRECTION INPUT ;
    USE SIGNAL ;
    ANTENNAGATEAREA 0.196500 ;
    ANTENNADIFFAREA 0.434700 ;
    PORT
      LAYER met3 ;
        RECT 0.000 112.920 4.000 113.520 ;
    END
  END wbs_adr_i[5]
  PIN wbs_adr_i[6]
    DIRECTION INPUT ;
    USE SIGNAL ;
    ANTENNAGATEAREA 0.196500 ;
    ANTENNADIFFAREA 0.434700 ;
    PORT
      LAYER met3 ;
        RECT 0.000 118.360 4.000 118.960 ;
    END
  END wbs_adr_i[6]
  PIN wbs_adr_i[7]
    DIRECTION INPUT ;
    USE SIGNAL ;
    ANTENNAGATEAREA 0.196500 ;
    ANTENNADIFFAREA 0.434700 ;
    PORT
      LAYER met3 ;
        RECT 0.000 123.800 4.000 124.400 ;
    END
  END wbs_adr_i[7]
  PIN wbs_adr_i[8]
    DIRECTION INPUT ;
    USE SIGNAL ;
    PORT
      LAYER met3 ;
        RECT 0.000 129.240 4.000 129.840 ;
    END
  END wbs_adr_i[8]
  PIN wbs_adr_i[9]
    DIRECTION INPUT ;
    USE SIGNAL ;
    PORT
      LAYER met3 ;
        RECT 0.000 134.680 4.000 135.280 ;
    END
  END wbs_adr_i[9]
  PIN wbs_cyc_i
    DIRECTION INPUT ;
    USE SIGNAL ;
    ANTENNAGATEAREA 0.196500 ;
    ANTENNADIFFAREA 0.434700 ;
    PORT
      LAYER met3 ;
        RECT 0.000 47.640 4.000 48.240 ;
    END
  END wbs_cyc_i
  PIN wbs_dat_i[0]
    DIRECTION INPUT ;
    USE SIGNAL ;
    ANTENNAGATEAREA 0.196500 ;
    ANTENNADIFFAREA 0.434700 ;
    PORT
      LAYER met3 ;
        RECT 0.000 259.800 4.000 260.400 ;
    END
  END wbs_dat_i[0]
  PIN wbs_dat_i[10]
    DIRECTION INPUT ;
    USE SIGNAL ;
    ANTENNAGATEAREA 0.196500 ;
    ANTENNADIFFAREA 0.434700 ;
    PORT
      LAYER met3 ;
        RECT 0.000 314.200 4.000 314.800 ;
    END
  END wbs_dat_i[10]
  PIN wbs_dat_i[11]
    DIRECTION INPUT ;
    USE SIGNAL ;
    ANTENNAGATEAREA 0.196500 ;
    ANTENNADIFFAREA 0.434700 ;
    PORT
      LAYER met3 ;
        RECT 0.000 319.640 4.000 320.240 ;
    END
  END wbs_dat_i[11]
  PIN wbs_dat_i[12]
    DIRECTION INPUT ;
    USE SIGNAL ;
    ANTENNAGATEAREA 0.196500 ;
    ANTENNADIFFAREA 0.434700 ;
    PORT
      LAYER met3 ;
        RECT 0.000 325.080 4.000 325.680 ;
    END
  END wbs_dat_i[12]
  PIN wbs_dat_i[13]
    DIRECTION INPUT ;
    USE SIGNAL ;
    ANTENNAGATEAREA 0.196500 ;
    ANTENNADIFFAREA 0.434700 ;
    PORT
      LAYER met3 ;
        RECT 0.000 330.520 4.000 331.120 ;
    END
  END wbs_dat_i[13]
  PIN wbs_dat_i[14]
    DIRECTION INPUT ;
    USE SIGNAL ;
    ANTENNAGATEAREA 0.196500 ;
    ANTENNADIFFAREA 0.434700 ;
    PORT
      LAYER met3 ;
        RECT 0.000 335.960 4.000 336.560 ;
    END
  END wbs_dat_i[14]
  PIN wbs_dat_i[15]
    DIRECTION INPUT ;
    USE SIGNAL ;
    ANTENNAGATEAREA 0.196500 ;
    ANTENNADIFFAREA 0.434700 ;
    PORT
      LAYER met3 ;
        RECT 0.000 341.400 4.000 342.000 ;
    END
  END wbs_dat_i[15]
  PIN wbs_dat_i[16]
    DIRECTION INPUT ;
    USE SIGNAL ;
    ANTENNAGATEAREA 0.196500 ;
    ANTENNADIFFAREA 0.434700 ;
    PORT
      LAYER met3 ;
        RECT 0.000 346.840 4.000 347.440 ;
    END
  END wbs_dat_i[16]
  PIN wbs_dat_i[17]
    DIRECTION INPUT ;
    USE SIGNAL ;
    ANTENNAGATEAREA 0.196500 ;
    ANTENNADIFFAREA 0.434700 ;
    PORT
      LAYER met3 ;
        RECT 0.000 352.280 4.000 352.880 ;
    END
  END wbs_dat_i[17]
  PIN wbs_dat_i[18]
    DIRECTION INPUT ;
    USE SIGNAL ;
    ANTENNAGATEAREA 0.196500 ;
    ANTENNADIFFAREA 0.434700 ;
    PORT
      LAYER met3 ;
        RECT 0.000 357.720 4.000 358.320 ;
    END
  END wbs_dat_i[18]
  PIN wbs_dat_i[19]
    DIRECTION INPUT ;
    USE SIGNAL ;
    ANTENNAGATEAREA 0.196500 ;
    ANTENNADIFFAREA 0.434700 ;
    PORT
      LAYER met3 ;
        RECT 0.000 363.160 4.000 363.760 ;
    END
  END wbs_dat_i[19]
  PIN wbs_dat_i[1]
    DIRECTION INPUT ;
    USE SIGNAL ;
    ANTENNAGATEAREA 0.196500 ;
    ANTENNADIFFAREA 0.434700 ;
    PORT
      LAYER met3 ;
        RECT 0.000 265.240 4.000 265.840 ;
    END
  END wbs_dat_i[1]
  PIN wbs_dat_i[20]
    DIRECTION INPUT ;
    USE SIGNAL ;
    ANTENNAGATEAREA 0.196500 ;
    ANTENNADIFFAREA 0.434700 ;
    PORT
      LAYER met3 ;
        RECT 0.000 368.600 4.000 369.200 ;
    END
  END wbs_dat_i[20]
  PIN wbs_dat_i[21]
    DIRECTION INPUT ;
    USE SIGNAL ;
    ANTENNAGATEAREA 0.196500 ;
    ANTENNADIFFAREA 0.434700 ;
    PORT
      LAYER met3 ;
        RECT 0.000 374.040 4.000 374.640 ;
    END
  END wbs_dat_i[21]
  PIN wbs_dat_i[22]
    DIRECTION INPUT ;
    USE SIGNAL ;
    ANTENNAGATEAREA 0.196500 ;
    ANTENNADIFFAREA 0.434700 ;
    PORT
      LAYER met3 ;
        RECT 0.000 379.480 4.000 380.080 ;
    END
  END wbs_dat_i[22]
  PIN wbs_dat_i[23]
    DIRECTION INPUT ;
    USE SIGNAL ;
    ANTENNAGATEAREA 0.196500 ;
    ANTENNADIFFAREA 0.434700 ;
    PORT
      LAYER met3 ;
        RECT 0.000 384.920 4.000 385.520 ;
    END
  END wbs_dat_i[23]
  PIN wbs_dat_i[24]
    DIRECTION INPUT ;
    USE SIGNAL ;
    ANTENNAGATEAREA 0.196500 ;
    ANTENNADIFFAREA 0.434700 ;
    PORT
      LAYER met3 ;
        RECT 0.000 390.360 4.000 390.960 ;
    END
  END wbs_dat_i[24]
  PIN wbs_dat_i[25]
    DIRECTION INPUT ;
    USE SIGNAL ;
    ANTENNAGATEAREA 0.196500 ;
    ANTENNADIFFAREA 0.434700 ;
    PORT
      LAYER met3 ;
        RECT 0.000 395.800 4.000 396.400 ;
    END
  END wbs_dat_i[25]
  PIN wbs_dat_i[26]
    DIRECTION INPUT ;
    USE SIGNAL ;
    ANTENNAGATEAREA 0.196500 ;
    ANTENNADIFFAREA 0.434700 ;
    PORT
      LAYER met3 ;
        RECT 0.000 401.240 4.000 401.840 ;
    END
  END wbs_dat_i[26]
  PIN wbs_dat_i[27]
    DIRECTION INPUT ;
    USE SIGNAL ;
    ANTENNAGATEAREA 0.196500 ;
    ANTENNADIFFAREA 0.434700 ;
    PORT
      LAYER met3 ;
        RECT 0.000 406.680 4.000 407.280 ;
    END
  END wbs_dat_i[27]
  PIN wbs_dat_i[28]
    DIRECTION INPUT ;
    USE SIGNAL ;
    ANTENNAGATEAREA 0.196500 ;
    ANTENNADIFFAREA 0.434700 ;
    PORT
      LAYER met3 ;
        RECT 0.000 412.120 4.000 412.720 ;
    END
  END wbs_dat_i[28]
  PIN wbs_dat_i[29]
    DIRECTION INPUT ;
    USE SIGNAL ;
    ANTENNAGATEAREA 0.196500 ;
    ANTENNADIFFAREA 0.434700 ;
    PORT
      LAYER met3 ;
        RECT 0.000 417.560 4.000 418.160 ;
    END
  END wbs_dat_i[29]
  PIN wbs_dat_i[2]
    DIRECTION INPUT ;
    USE SIGNAL ;
    ANTENNAGATEAREA 0.196500 ;
    ANTENNADIFFAREA 0.434700 ;
    PORT
      LAYER met3 ;
        RECT 0.000 270.680 4.000 271.280 ;
    END
  END wbs_dat_i[2]
  PIN wbs_dat_i[30]
    DIRECTION INPUT ;
    USE SIGNAL ;
    ANTENNAGATEAREA 0.196500 ;
    ANTENNADIFFAREA 0.434700 ;
    PORT
      LAYER met3 ;
        RECT 0.000 423.000 4.000 423.600 ;
    END
  END wbs_dat_i[30]
  PIN wbs_dat_i[31]
    DIRECTION INPUT ;
    USE SIGNAL ;
    ANTENNAGATEAREA 0.196500 ;
    ANTENNADIFFAREA 0.434700 ;
    PORT
      LAYER met3 ;
        RECT 0.000 428.440 4.000 429.040 ;
    END
  END wbs_dat_i[31]
  PIN wbs_dat_i[3]
    DIRECTION INPUT ;
    USE SIGNAL ;
    ANTENNAGATEAREA 0.196500 ;
    ANTENNADIFFAREA 0.434700 ;
    PORT
      LAYER met3 ;
        RECT 0.000 276.120 4.000 276.720 ;
    END
  END wbs_dat_i[3]
  PIN wbs_dat_i[4]
    DIRECTION INPUT ;
    USE SIGNAL ;
    ANTENNAGATEAREA 0.196500 ;
    ANTENNADIFFAREA 0.434700 ;
    PORT
      LAYER met3 ;
        RECT 0.000 281.560 4.000 282.160 ;
    END
  END wbs_dat_i[4]
  PIN wbs_dat_i[5]
    DIRECTION INPUT ;
    USE SIGNAL ;
    ANTENNAGATEAREA 0.196500 ;
    ANTENNADIFFAREA 0.434700 ;
    PORT
      LAYER met3 ;
        RECT 0.000 287.000 4.000 287.600 ;
    END
  END wbs_dat_i[5]
  PIN wbs_dat_i[6]
    DIRECTION INPUT ;
    USE SIGNAL ;
    ANTENNAGATEAREA 0.196500 ;
    ANTENNADIFFAREA 0.434700 ;
    PORT
      LAYER met3 ;
        RECT 0.000 292.440 4.000 293.040 ;
    END
  END wbs_dat_i[6]
  PIN wbs_dat_i[7]
    DIRECTION INPUT ;
    USE SIGNAL ;
    ANTENNAGATEAREA 0.196500 ;
    ANTENNADIFFAREA 0.434700 ;
    PORT
      LAYER met3 ;
        RECT 0.000 297.880 4.000 298.480 ;
    END
  END wbs_dat_i[7]
  PIN wbs_dat_i[8]
    DIRECTION INPUT ;
    USE SIGNAL ;
    ANTENNAGATEAREA 0.196500 ;
    ANTENNADIFFAREA 0.434700 ;
    PORT
      LAYER met3 ;
        RECT 0.000 303.320 4.000 303.920 ;
    END
  END wbs_dat_i[8]
  PIN wbs_dat_i[9]
    DIRECTION INPUT ;
    USE SIGNAL ;
    ANTENNAGATEAREA 0.196500 ;
    ANTENNADIFFAREA 0.434700 ;
    PORT
      LAYER met3 ;
        RECT 0.000 308.760 4.000 309.360 ;
    END
  END wbs_dat_i[9]
  PIN wbs_dat_o[0]
    DIRECTION OUTPUT TRISTATE ;
    USE SIGNAL ;
    ANTENNADIFFAREA 3.180800 ;
    PORT
      LAYER met3 ;
        RECT 0.000 439.320 4.000 439.920 ;
    END
  END wbs_dat_o[0]
  PIN wbs_dat_o[10]
    DIRECTION OUTPUT TRISTATE ;
    USE SIGNAL ;
    ANTENNADIFFAREA 3.180800 ;
    PORT
      LAYER met3 ;
        RECT 0.000 493.720 4.000 494.320 ;
    END
  END wbs_dat_o[10]
  PIN wbs_dat_o[11]
    DIRECTION OUTPUT TRISTATE ;
    USE SIGNAL ;
    ANTENNADIFFAREA 3.180800 ;
    PORT
      LAYER met3 ;
        RECT 0.000 499.160 4.000 499.760 ;
    END
  END wbs_dat_o[11]
  PIN wbs_dat_o[12]
    DIRECTION OUTPUT TRISTATE ;
    USE SIGNAL ;
    ANTENNADIFFAREA 3.180800 ;
    PORT
      LAYER met3 ;
        RECT 0.000 504.600 4.000 505.200 ;
    END
  END wbs_dat_o[12]
  PIN wbs_dat_o[13]
    DIRECTION OUTPUT TRISTATE ;
    USE SIGNAL ;
    ANTENNADIFFAREA 3.180800 ;
    PORT
      LAYER met3 ;
        RECT 0.000 510.040 4.000 510.640 ;
    END
  END wbs_dat_o[13]
  PIN wbs_dat_o[14]
    DIRECTION OUTPUT TRISTATE ;
    USE SIGNAL ;
    ANTENNADIFFAREA 3.180800 ;
    PORT
      LAYER met3 ;
        RECT 0.000 515.480 4.000 516.080 ;
    END
  END wbs_dat_o[14]
  PIN wbs_dat_o[15]
    DIRECTION OUTPUT TRISTATE ;
    USE SIGNAL ;
    ANTENNADIFFAREA 3.180800 ;
    PORT
      LAYER met3 ;
        RECT 0.000 520.920 4.000 521.520 ;
    END
  END wbs_dat_o[15]
  PIN wbs_dat_o[16]
    DIRECTION OUTPUT TRISTATE ;
    USE SIGNAL ;
    ANTENNADIFFAREA 3.180800 ;
    PORT
      LAYER met3 ;
        RECT 0.000 526.360 4.000 526.960 ;
    END
  END wbs_dat_o[16]
  PIN wbs_dat_o[17]
    DIRECTION OUTPUT TRISTATE ;
    USE SIGNAL ;
    ANTENNADIFFAREA 3.180800 ;
    PORT
      LAYER met3 ;
        RECT 0.000 531.800 4.000 532.400 ;
    END
  END wbs_dat_o[17]
  PIN wbs_dat_o[18]
    DIRECTION OUTPUT TRISTATE ;
    USE SIGNAL ;
    ANTENNADIFFAREA 3.180800 ;
    PORT
      LAYER met3 ;
        RECT 0.000 537.240 4.000 537.840 ;
    END
  END wbs_dat_o[18]
  PIN wbs_dat_o[19]
    DIRECTION OUTPUT TRISTATE ;
    USE SIGNAL ;
    ANTENNADIFFAREA 3.180800 ;
    PORT
      LAYER met3 ;
        RECT 0.000 542.680 4.000 543.280 ;
    END
  END wbs_dat_o[19]
  PIN wbs_dat_o[1]
    DIRECTION OUTPUT TRISTATE ;
    USE SIGNAL ;
    ANTENNADIFFAREA 3.180800 ;
    PORT
      LAYER met3 ;
        RECT 0.000 444.760 4.000 445.360 ;
    END
  END wbs_dat_o[1]
  PIN wbs_dat_o[20]
    DIRECTION OUTPUT TRISTATE ;
    USE SIGNAL ;
    ANTENNADIFFAREA 3.180800 ;
    PORT
      LAYER met3 ;
        RECT 0.000 548.120 4.000 548.720 ;
    END
  END wbs_dat_o[20]
  PIN wbs_dat_o[21]
    DIRECTION OUTPUT TRISTATE ;
    USE SIGNAL ;
    ANTENNADIFFAREA 3.180800 ;
    PORT
      LAYER met3 ;
        RECT 0.000 553.560 4.000 554.160 ;
    END
  END wbs_dat_o[21]
  PIN wbs_dat_o[22]
    DIRECTION OUTPUT TRISTATE ;
    USE SIGNAL ;
    ANTENNADIFFAREA 3.180800 ;
    PORT
      LAYER met3 ;
        RECT 0.000 559.000 4.000 559.600 ;
    END
  END wbs_dat_o[22]
  PIN wbs_dat_o[23]
    DIRECTION OUTPUT TRISTATE ;
    USE SIGNAL ;
    ANTENNADIFFAREA 3.180800 ;
    PORT
      LAYER met3 ;
        RECT 0.000 564.440 4.000 565.040 ;
    END
  END wbs_dat_o[23]
  PIN wbs_dat_o[24]
    DIRECTION OUTPUT TRISTATE ;
    USE SIGNAL ;
    ANTENNADIFFAREA 3.180800 ;
    PORT
      LAYER met3 ;
        RECT 0.000 569.880 4.000 570.480 ;
    END
  END wbs_dat_o[24]
  PIN wbs_dat_o[25]
    DIRECTION OUTPUT TRISTATE ;
    USE SIGNAL ;
    ANTENNADIFFAREA 3.180800 ;
    PORT
      LAYER met3 ;
        RECT 0.000 575.320 4.000 575.920 ;
    END
  END wbs_dat_o[25]
  PIN wbs_dat_o[26]
    DIRECTION OUTPUT TRISTATE ;
    USE SIGNAL ;
    ANTENNADIFFAREA 3.180800 ;
    PORT
      LAYER met3 ;
        RECT 0.000 580.760 4.000 581.360 ;
    END
  END wbs_dat_o[26]
  PIN wbs_dat_o[27]
    DIRECTION OUTPUT TRISTATE ;
    USE SIGNAL ;
    ANTENNADIFFAREA 3.180800 ;
    PORT
      LAYER met3 ;
        RECT 0.000 586.200 4.000 586.800 ;
    END
  END wbs_dat_o[27]
  PIN wbs_dat_o[28]
    DIRECTION OUTPUT TRISTATE ;
    USE SIGNAL ;
    ANTENNADIFFAREA 3.180800 ;
    PORT
      LAYER met3 ;
        RECT 0.000 591.640 4.000 592.240 ;
    END
  END wbs_dat_o[28]
  PIN wbs_dat_o[29]
    DIRECTION OUTPUT TRISTATE ;
    USE SIGNAL ;
    ANTENNADIFFAREA 3.180800 ;
    PORT
      LAYER met3 ;
        RECT 0.000 597.080 4.000 597.680 ;
    END
  END wbs_dat_o[29]
  PIN wbs_dat_o[2]
    DIRECTION OUTPUT TRISTATE ;
    USE SIGNAL ;
    ANTENNADIFFAREA 3.180800 ;
    PORT
      LAYER met3 ;
        RECT 0.000 450.200 4.000 450.800 ;
    END
  END wbs_dat_o[2]
  PIN wbs_dat_o[30]
    DIRECTION OUTPUT TRISTATE ;
    USE SIGNAL ;
    ANTENNADIFFAREA 3.180800 ;
    PORT
      LAYER met3 ;
        RECT 0.000 602.520 4.000 603.120 ;
    END
  END wbs_dat_o[30]
  PIN wbs_dat_o[31]
    DIRECTION OUTPUT TRISTATE ;
    USE SIGNAL ;
    ANTENNADIFFAREA 3.180800 ;
    PORT
      LAYER met3 ;
        RECT 0.000 607.960 4.000 608.560 ;
    END
  END wbs_dat_o[31]
  PIN wbs_dat_o[3]
    DIRECTION OUTPUT TRISTATE ;
    USE SIGNAL ;
    ANTENNADIFFAREA 3.180800 ;
    PORT
      LAYER met3 ;
        RECT 0.000 455.640 4.000 456.240 ;
    END
  END wbs_dat_o[3]
  PIN wbs_dat_o[4]
    DIRECTION OUTPUT TRISTATE ;
    USE SIGNAL ;
    ANTENNADIFFAREA 3.180800 ;
    PORT
      LAYER met3 ;
        RECT 0.000 461.080 4.000 461.680 ;
    END
  END wbs_dat_o[4]
  PIN wbs_dat_o[5]
    DIRECTION OUTPUT TRISTATE ;
    USE SIGNAL ;
    ANTENNADIFFAREA 3.180800 ;
    PORT
      LAYER met3 ;
        RECT 0.000 466.520 4.000 467.120 ;
    END
  END wbs_dat_o[5]
  PIN wbs_dat_o[6]
    DIRECTION OUTPUT TRISTATE ;
    USE SIGNAL ;
    ANTENNADIFFAREA 3.180800 ;
    PORT
      LAYER met3 ;
        RECT 0.000 471.960 4.000 472.560 ;
    END
  END wbs_dat_o[6]
  PIN wbs_dat_o[7]
    DIRECTION OUTPUT TRISTATE ;
    USE SIGNAL ;
    ANTENNADIFFAREA 3.180800 ;
    PORT
      LAYER met3 ;
        RECT 0.000 477.400 4.000 478.000 ;
    END
  END wbs_dat_o[7]
  PIN wbs_dat_o[8]
    DIRECTION OUTPUT TRISTATE ;
    USE SIGNAL ;
    ANTENNADIFFAREA 3.180800 ;
    PORT
      LAYER met3 ;
        RECT 0.000 482.840 4.000 483.440 ;
    END
  END wbs_dat_o[8]
  PIN wbs_dat_o[9]
    DIRECTION OUTPUT TRISTATE ;
    USE SIGNAL ;
    ANTENNADIFFAREA 3.180800 ;
    PORT
      LAYER met3 ;
        RECT 0.000 488.280 4.000 488.880 ;
    END
  END wbs_dat_o[9]
  PIN wbs_sel_i[0]
    DIRECTION INPUT ;
    USE SIGNAL ;
    ANTENNAGATEAREA 0.196500 ;
    ANTENNADIFFAREA 0.434700 ;
    PORT
      LAYER met3 ;
        RECT 0.000 63.960 4.000 64.560 ;
    END
  END wbs_sel_i[0]
  PIN wbs_sel_i[1]
    DIRECTION INPUT ;
    USE SIGNAL ;
    ANTENNAGATEAREA 0.196500 ;
    ANTENNADIFFAREA 0.434700 ;
    PORT
      LAYER met3 ;
        RECT 0.000 69.400 4.000 70.000 ;
    END
  END wbs_sel_i[1]
  PIN wbs_sel_i[2]
    DIRECTION INPUT ;
    USE SIGNAL ;
    ANTENNAGATEAREA 0.196500 ;
    ANTENNADIFFAREA 0.434700 ;
    PORT
      LAYER met3 ;
        RECT 0.000 74.840 4.000 75.440 ;
    END
  END wbs_sel_i[2]
  PIN wbs_sel_i[3]
    DIRECTION INPUT ;
    USE SIGNAL ;
    ANTENNAGATEAREA 0.196500 ;
    ANTENNADIFFAREA 0.434700 ;
    PORT
      LAYER met3 ;
        RECT 0.000 80.280 4.000 80.880 ;
    END
  END wbs_sel_i[3]
  PIN wbs_stb_i
    DIRECTION INPUT ;
    USE SIGNAL ;
    ANTENNAGATEAREA 0.196500 ;
    ANTENNADIFFAREA 0.434700 ;
    PORT
      LAYER met3 ;
        RECT 0.000 53.080 4.000 53.680 ;
    END
  END wbs_stb_i
  PIN wbs_we_i
    DIRECTION INPUT ;
    USE SIGNAL ;
    ANTENNAGATEAREA 0.196500 ;
    ANTENNADIFFAREA 0.434700 ;
    PORT
      LAYER met3 ;
        RECT 0.000 58.520 4.000 59.120 ;
    END
  END wbs_we_i
  OBS
      LAYER li1 ;
        RECT 15.180 16.235 984.860 783.445 ;
      LAYER met1 ;
        RECT 12.030 16.080 984.860 783.600 ;
      LAYER met2 ;
        RECT 3.770 2.875 987.070 797.485 ;
      LAYER met3 ;
        RECT 3.745 795.600 19.510 797.465 ;
        RECT 20.610 795.600 29.710 797.465 ;
        RECT 30.810 795.600 39.910 797.465 ;
        RECT 41.010 795.600 50.110 797.465 ;
        RECT 51.210 795.600 60.310 797.465 ;
        RECT 61.410 795.600 70.510 797.465 ;
        RECT 71.610 795.600 80.710 797.465 ;
        RECT 81.810 795.600 90.910 797.465 ;
        RECT 92.010 795.600 101.110 797.465 ;
        RECT 102.210 795.600 111.310 797.465 ;
        RECT 112.410 795.600 121.510 797.465 ;
        RECT 122.610 795.600 131.710 797.465 ;
        RECT 132.810 795.600 141.910 797.465 ;
        RECT 143.010 795.600 152.110 797.465 ;
        RECT 153.210 795.600 162.310 797.465 ;
        RECT 163.410 795.600 172.510 797.465 ;
        RECT 173.610 795.600 182.710 797.465 ;
        RECT 183.810 795.600 192.910 797.465 ;
        RECT 194.010 795.600 203.110 797.465 ;
        RECT 204.210 795.600 213.310 797.465 ;
        RECT 214.410 795.600 223.510 797.465 ;
        RECT 224.610 795.600 233.710 797.465 ;
        RECT 234.810 795.600 243.910 797.465 ;
        RECT 245.010 795.600 254.110 797.465 ;
        RECT 255.210 795.600 264.310 797.465 ;
        RECT 265.410 795.600 274.510 797.465 ;
        RECT 275.610 795.600 284.710 797.465 ;
        RECT 285.810 795.600 294.910 797.465 ;
        RECT 296.010 795.600 305.110 797.465 ;
        RECT 306.210 795.600 315.310 797.465 ;
        RECT 316.410 795.600 325.510 797.465 ;
        RECT 326.610 795.600 335.710 797.465 ;
        RECT 336.810 795.600 345.910 797.465 ;
        RECT 347.010 795.600 356.110 797.465 ;
        RECT 357.210 795.600 366.310 797.465 ;
        RECT 367.410 795.600 376.510 797.465 ;
        RECT 377.610 795.600 386.710 797.465 ;
        RECT 387.810 795.600 396.910 797.465 ;
        RECT 398.010 795.600 407.110 797.465 ;
        RECT 408.210 795.600 417.310 797.465 ;
        RECT 418.410 795.600 427.510 797.465 ;
        RECT 428.610 795.600 437.710 797.465 ;
        RECT 438.810 795.600 447.910 797.465 ;
        RECT 449.010 795.600 458.110 797.465 ;
        RECT 459.210 795.600 468.310 797.465 ;
        RECT 469.410 795.600 478.510 797.465 ;
        RECT 479.610 795.600 488.710 797.465 ;
        RECT 489.810 795.600 498.910 797.465 ;
        RECT 500.010 795.600 509.110 797.465 ;
        RECT 510.210 795.600 519.310 797.465 ;
        RECT 520.410 795.600 529.510 797.465 ;
        RECT 530.610 795.600 539.710 797.465 ;
        RECT 540.810 795.600 549.910 797.465 ;
        RECT 551.010 795.600 560.110 797.465 ;
        RECT 561.210 795.600 570.310 797.465 ;
        RECT 571.410 795.600 580.510 797.465 ;
        RECT 581.610 795.600 590.710 797.465 ;
        RECT 591.810 795.600 600.910 797.465 ;
        RECT 602.010 795.600 611.110 797.465 ;
        RECT 612.210 795.600 621.310 797.465 ;
        RECT 622.410 795.600 631.510 797.465 ;
        RECT 632.610 795.600 641.710 797.465 ;
        RECT 642.810 795.600 651.910 797.465 ;
        RECT 653.010 795.600 662.110 797.465 ;
        RECT 663.210 795.600 672.310 797.465 ;
        RECT 673.410 795.600 682.510 797.465 ;
        RECT 683.610 795.600 692.710 797.465 ;
        RECT 693.810 795.600 702.910 797.465 ;
        RECT 704.010 795.600 713.110 797.465 ;
        RECT 714.210 795.600 723.310 797.465 ;
        RECT 724.410 795.600 733.510 797.465 ;
        RECT 734.610 795.600 743.710 797.465 ;
        RECT 744.810 795.600 753.910 797.465 ;
        RECT 755.010 795.600 764.110 797.465 ;
        RECT 765.210 795.600 774.310 797.465 ;
        RECT 775.410 795.600 784.510 797.465 ;
        RECT 785.610 795.600 794.710 797.465 ;
        RECT 795.810 795.600 804.910 797.465 ;
        RECT 806.010 795.600 815.110 797.465 ;
        RECT 816.210 795.600 825.310 797.465 ;
        RECT 826.410 795.600 835.510 797.465 ;
        RECT 836.610 795.600 845.710 797.465 ;
        RECT 846.810 795.600 855.910 797.465 ;
        RECT 857.010 795.600 866.110 797.465 ;
        RECT 867.210 795.600 876.310 797.465 ;
        RECT 877.410 795.600 886.510 797.465 ;
        RECT 887.610 795.600 896.710 797.465 ;
        RECT 897.810 795.600 906.910 797.465 ;
        RECT 908.010 795.600 917.110 797.465 ;
        RECT 918.210 795.600 927.310 797.465 ;
        RECT 928.410 795.600 937.510 797.465 ;
        RECT 938.610 795.600 947.710 797.465 ;
        RECT 948.810 795.600 957.910 797.465 ;
        RECT 959.010 795.600 968.110 797.465 ;
        RECT 969.210 795.600 978.310 797.465 ;
        RECT 979.410 795.600 996.000 797.465 ;
        RECT 3.745 783.040 996.000 795.600 ;
        RECT 3.745 781.640 995.600 783.040 ;
        RECT 3.745 766.720 996.000 781.640 ;
        RECT 3.745 765.320 995.600 766.720 ;
        RECT 3.745 761.280 996.000 765.320 ;
        RECT 4.400 759.880 996.000 761.280 ;
        RECT 3.745 755.840 996.000 759.880 ;
        RECT 4.400 754.440 996.000 755.840 ;
        RECT 3.745 750.400 996.000 754.440 ;
        RECT 4.400 749.000 995.600 750.400 ;
        RECT 3.745 744.960 996.000 749.000 ;
        RECT 4.400 743.560 996.000 744.960 ;
        RECT 3.745 739.520 996.000 743.560 ;
        RECT 4.400 738.120 996.000 739.520 ;
        RECT 3.745 734.080 996.000 738.120 ;
        RECT 4.400 732.680 995.600 734.080 ;
        RECT 3.745 728.640 996.000 732.680 ;
        RECT 4.400 727.240 996.000 728.640 ;
        RECT 3.745 723.200 996.000 727.240 ;
        RECT 4.400 721.800 996.000 723.200 ;
        RECT 3.745 717.760 996.000 721.800 ;
        RECT 4.400 716.360 995.600 717.760 ;
        RECT 3.745 712.320 996.000 716.360 ;
        RECT 4.400 710.920 996.000 712.320 ;
        RECT 3.745 706.880 996.000 710.920 ;
        RECT 4.400 705.480 996.000 706.880 ;
        RECT 3.745 701.440 996.000 705.480 ;
        RECT 4.400 700.040 995.600 701.440 ;
        RECT 3.745 696.000 996.000 700.040 ;
        RECT 4.400 694.600 996.000 696.000 ;
        RECT 3.745 690.560 996.000 694.600 ;
        RECT 4.400 689.160 996.000 690.560 ;
        RECT 3.745 685.120 996.000 689.160 ;
        RECT 4.400 683.720 995.600 685.120 ;
        RECT 3.745 679.680 996.000 683.720 ;
        RECT 4.400 678.280 996.000 679.680 ;
        RECT 3.745 674.240 996.000 678.280 ;
        RECT 4.400 672.840 996.000 674.240 ;
        RECT 3.745 668.800 996.000 672.840 ;
        RECT 4.400 667.400 995.600 668.800 ;
        RECT 3.745 663.360 996.000 667.400 ;
        RECT 4.400 661.960 996.000 663.360 ;
        RECT 3.745 657.920 996.000 661.960 ;
        RECT 4.400 656.520 996.000 657.920 ;
        RECT 3.745 652.480 996.000 656.520 ;
        RECT 4.400 651.080 995.600 652.480 ;
        RECT 3.745 647.040 996.000 651.080 ;
        RECT 4.400 645.640 996.000 647.040 ;
        RECT 3.745 641.600 996.000 645.640 ;
        RECT 4.400 640.200 996.000 641.600 ;
        RECT 3.745 636.160 996.000 640.200 ;
        RECT 4.400 634.760 995.600 636.160 ;
        RECT 3.745 630.720 996.000 634.760 ;
        RECT 4.400 629.320 996.000 630.720 ;
        RECT 3.745 625.280 996.000 629.320 ;
        RECT 4.400 623.880 996.000 625.280 ;
        RECT 3.745 619.840 996.000 623.880 ;
        RECT 4.400 618.440 995.600 619.840 ;
        RECT 3.745 614.400 996.000 618.440 ;
        RECT 4.400 613.000 996.000 614.400 ;
        RECT 3.745 608.960 996.000 613.000 ;
        RECT 4.400 607.560 996.000 608.960 ;
        RECT 3.745 603.520 996.000 607.560 ;
        RECT 4.400 602.120 995.600 603.520 ;
        RECT 3.745 598.080 996.000 602.120 ;
        RECT 4.400 596.680 996.000 598.080 ;
        RECT 3.745 592.640 996.000 596.680 ;
        RECT 4.400 591.240 996.000 592.640 ;
        RECT 3.745 587.200 996.000 591.240 ;
        RECT 4.400 585.800 995.600 587.200 ;
        RECT 3.745 581.760 996.000 585.800 ;
        RECT 4.400 580.360 996.000 581.760 ;
        RECT 3.745 576.320 996.000 580.360 ;
        RECT 4.400 574.920 996.000 576.320 ;
        RECT 3.745 570.880 996.000 574.920 ;
        RECT 4.400 569.480 995.600 570.880 ;
        RECT 3.745 565.440 996.000 569.480 ;
        RECT 4.400 564.040 996.000 565.440 ;
        RECT 3.745 560.000 996.000 564.040 ;
        RECT 4.400 558.600 996.000 560.000 ;
        RECT 3.745 554.560 996.000 558.600 ;
        RECT 4.400 553.160 995.600 554.560 ;
        RECT 3.745 549.120 996.000 553.160 ;
        RECT 4.400 547.720 996.000 549.120 ;
        RECT 3.745 543.680 996.000 547.720 ;
        RECT 4.400 542.280 996.000 543.680 ;
        RECT 3.745 538.240 996.000 542.280 ;
        RECT 4.400 536.840 995.600 538.240 ;
        RECT 3.745 532.800 996.000 536.840 ;
        RECT 4.400 531.400 996.000 532.800 ;
        RECT 3.745 527.360 996.000 531.400 ;
        RECT 4.400 525.960 996.000 527.360 ;
        RECT 3.745 521.920 996.000 525.960 ;
        RECT 4.400 520.520 995.600 521.920 ;
        RECT 3.745 516.480 996.000 520.520 ;
        RECT 4.400 515.080 996.000 516.480 ;
        RECT 3.745 511.040 996.000 515.080 ;
        RECT 4.400 509.640 996.000 511.040 ;
        RECT 3.745 505.600 996.000 509.640 ;
        RECT 4.400 504.200 995.600 505.600 ;
        RECT 3.745 500.160 996.000 504.200 ;
        RECT 4.400 498.760 996.000 500.160 ;
        RECT 3.745 494.720 996.000 498.760 ;
        RECT 4.400 493.320 996.000 494.720 ;
        RECT 3.745 489.280 996.000 493.320 ;
        RECT 4.400 487.880 995.600 489.280 ;
        RECT 3.745 483.840 996.000 487.880 ;
        RECT 4.400 482.440 996.000 483.840 ;
        RECT 3.745 478.400 996.000 482.440 ;
        RECT 4.400 477.000 996.000 478.400 ;
        RECT 3.745 472.960 996.000 477.000 ;
        RECT 4.400 471.560 995.600 472.960 ;
        RECT 3.745 467.520 996.000 471.560 ;
        RECT 4.400 466.120 996.000 467.520 ;
        RECT 3.745 462.080 996.000 466.120 ;
        RECT 4.400 460.680 996.000 462.080 ;
        RECT 3.745 456.640 996.000 460.680 ;
        RECT 4.400 455.240 995.600 456.640 ;
        RECT 3.745 451.200 996.000 455.240 ;
        RECT 4.400 449.800 996.000 451.200 ;
        RECT 3.745 445.760 996.000 449.800 ;
        RECT 4.400 444.360 996.000 445.760 ;
        RECT 3.745 440.320 996.000 444.360 ;
        RECT 4.400 438.920 995.600 440.320 ;
        RECT 3.745 434.880 996.000 438.920 ;
        RECT 4.400 433.480 996.000 434.880 ;
        RECT 3.745 429.440 996.000 433.480 ;
        RECT 4.400 428.040 996.000 429.440 ;
        RECT 3.745 424.000 996.000 428.040 ;
        RECT 4.400 422.600 995.600 424.000 ;
        RECT 3.745 418.560 996.000 422.600 ;
        RECT 4.400 417.160 996.000 418.560 ;
        RECT 3.745 413.120 996.000 417.160 ;
        RECT 4.400 411.720 996.000 413.120 ;
        RECT 3.745 407.680 996.000 411.720 ;
        RECT 4.400 406.280 995.600 407.680 ;
        RECT 3.745 402.240 996.000 406.280 ;
        RECT 4.400 400.840 996.000 402.240 ;
        RECT 3.745 396.800 996.000 400.840 ;
        RECT 4.400 395.400 996.000 396.800 ;
        RECT 3.745 391.360 996.000 395.400 ;
        RECT 4.400 389.960 995.600 391.360 ;
        RECT 3.745 385.920 996.000 389.960 ;
        RECT 4.400 384.520 996.000 385.920 ;
        RECT 3.745 380.480 996.000 384.520 ;
        RECT 4.400 379.080 996.000 380.480 ;
        RECT 3.745 375.040 996.000 379.080 ;
        RECT 4.400 373.640 995.600 375.040 ;
        RECT 3.745 369.600 996.000 373.640 ;
        RECT 4.400 368.200 996.000 369.600 ;
        RECT 3.745 364.160 996.000 368.200 ;
        RECT 4.400 362.760 996.000 364.160 ;
        RECT 3.745 358.720 996.000 362.760 ;
        RECT 4.400 357.320 995.600 358.720 ;
        RECT 3.745 353.280 996.000 357.320 ;
        RECT 4.400 351.880 996.000 353.280 ;
        RECT 3.745 347.840 996.000 351.880 ;
        RECT 4.400 346.440 996.000 347.840 ;
        RECT 3.745 342.400 996.000 346.440 ;
        RECT 4.400 341.000 995.600 342.400 ;
        RECT 3.745 336.960 996.000 341.000 ;
        RECT 4.400 335.560 996.000 336.960 ;
        RECT 3.745 331.520 996.000 335.560 ;
        RECT 4.400 330.120 996.000 331.520 ;
        RECT 3.745 326.080 996.000 330.120 ;
        RECT 4.400 324.680 995.600 326.080 ;
        RECT 3.745 320.640 996.000 324.680 ;
        RECT 4.400 319.240 996.000 320.640 ;
        RECT 3.745 315.200 996.000 319.240 ;
        RECT 4.400 313.800 996.000 315.200 ;
        RECT 3.745 309.760 996.000 313.800 ;
        RECT 4.400 308.360 995.600 309.760 ;
        RECT 3.745 304.320 996.000 308.360 ;
        RECT 4.400 302.920 996.000 304.320 ;
        RECT 3.745 298.880 996.000 302.920 ;
        RECT 4.400 297.480 996.000 298.880 ;
        RECT 3.745 293.440 996.000 297.480 ;
        RECT 4.400 292.040 995.600 293.440 ;
        RECT 3.745 288.000 996.000 292.040 ;
        RECT 4.400 286.600 996.000 288.000 ;
        RECT 3.745 282.560 996.000 286.600 ;
        RECT 4.400 281.160 996.000 282.560 ;
        RECT 3.745 277.120 996.000 281.160 ;
        RECT 4.400 275.720 995.600 277.120 ;
        RECT 3.745 271.680 996.000 275.720 ;
        RECT 4.400 270.280 996.000 271.680 ;
        RECT 3.745 266.240 996.000 270.280 ;
        RECT 4.400 264.840 996.000 266.240 ;
        RECT 3.745 260.800 996.000 264.840 ;
        RECT 4.400 259.400 995.600 260.800 ;
        RECT 3.745 255.360 996.000 259.400 ;
        RECT 4.400 253.960 996.000 255.360 ;
        RECT 3.745 249.920 996.000 253.960 ;
        RECT 4.400 248.520 996.000 249.920 ;
        RECT 3.745 244.480 996.000 248.520 ;
        RECT 4.400 243.080 995.600 244.480 ;
        RECT 3.745 239.040 996.000 243.080 ;
        RECT 4.400 237.640 996.000 239.040 ;
        RECT 3.745 233.600 996.000 237.640 ;
        RECT 4.400 232.200 996.000 233.600 ;
        RECT 3.745 228.160 996.000 232.200 ;
        RECT 4.400 226.760 995.600 228.160 ;
        RECT 3.745 222.720 996.000 226.760 ;
        RECT 4.400 221.320 996.000 222.720 ;
        RECT 3.745 217.280 996.000 221.320 ;
        RECT 4.400 215.880 996.000 217.280 ;
        RECT 3.745 211.840 996.000 215.880 ;
        RECT 4.400 210.440 995.600 211.840 ;
        RECT 3.745 206.400 996.000 210.440 ;
        RECT 4.400 205.000 996.000 206.400 ;
        RECT 3.745 200.960 996.000 205.000 ;
        RECT 4.400 199.560 996.000 200.960 ;
        RECT 3.745 195.520 996.000 199.560 ;
        RECT 4.400 194.120 995.600 195.520 ;
        RECT 3.745 190.080 996.000 194.120 ;
        RECT 4.400 188.680 996.000 190.080 ;
        RECT 3.745 184.640 996.000 188.680 ;
        RECT 4.400 183.240 996.000 184.640 ;
        RECT 3.745 179.200 996.000 183.240 ;
        RECT 4.400 177.800 995.600 179.200 ;
        RECT 3.745 173.760 996.000 177.800 ;
        RECT 4.400 172.360 996.000 173.760 ;
        RECT 3.745 168.320 996.000 172.360 ;
        RECT 4.400 166.920 996.000 168.320 ;
        RECT 3.745 162.880 996.000 166.920 ;
        RECT 4.400 161.480 995.600 162.880 ;
        RECT 3.745 157.440 996.000 161.480 ;
        RECT 4.400 156.040 996.000 157.440 ;
        RECT 3.745 152.000 996.000 156.040 ;
        RECT 4.400 150.600 996.000 152.000 ;
        RECT 3.745 146.560 996.000 150.600 ;
        RECT 4.400 145.160 995.600 146.560 ;
        RECT 3.745 141.120 996.000 145.160 ;
        RECT 4.400 139.720 996.000 141.120 ;
        RECT 3.745 135.680 996.000 139.720 ;
        RECT 4.400 134.280 996.000 135.680 ;
        RECT 3.745 130.240 996.000 134.280 ;
        RECT 4.400 128.840 995.600 130.240 ;
        RECT 3.745 124.800 996.000 128.840 ;
        RECT 4.400 123.400 996.000 124.800 ;
        RECT 3.745 119.360 996.000 123.400 ;
        RECT 4.400 117.960 996.000 119.360 ;
        RECT 3.745 113.920 996.000 117.960 ;
        RECT 4.400 112.520 995.600 113.920 ;
        RECT 3.745 108.480 996.000 112.520 ;
        RECT 4.400 107.080 996.000 108.480 ;
        RECT 3.745 103.040 996.000 107.080 ;
        RECT 4.400 101.640 996.000 103.040 ;
        RECT 3.745 97.600 996.000 101.640 ;
        RECT 4.400 96.200 995.600 97.600 ;
        RECT 3.745 92.160 996.000 96.200 ;
        RECT 4.400 90.760 996.000 92.160 ;
        RECT 3.745 86.720 996.000 90.760 ;
        RECT 4.400 85.320 996.000 86.720 ;
        RECT 3.745 81.280 996.000 85.320 ;
        RECT 4.400 79.880 995.600 81.280 ;
        RECT 3.745 75.840 996.000 79.880 ;
        RECT 4.400 74.440 996.000 75.840 ;
        RECT 3.745 70.400 996.000 74.440 ;
        RECT 4.400 69.000 996.000 70.400 ;
        RECT 3.745 64.960 996.000 69.000 ;
        RECT 4.400 63.560 995.600 64.960 ;
        RECT 3.745 59.520 996.000 63.560 ;
        RECT 4.400 58.120 996.000 59.520 ;
        RECT 3.745 54.080 996.000 58.120 ;
        RECT 4.400 52.680 996.000 54.080 ;
        RECT 3.745 48.640 996.000 52.680 ;
        RECT 4.400 47.240 995.600 48.640 ;
        RECT 3.745 43.200 996.000 47.240 ;
        RECT 4.400 41.800 996.000 43.200 ;
        RECT 3.745 37.760 996.000 41.800 ;
        RECT 4.400 36.360 996.000 37.760 ;
        RECT 3.745 32.320 996.000 36.360 ;
        RECT 3.745 30.920 995.600 32.320 ;
        RECT 3.745 16.000 996.000 30.920 ;
        RECT 3.745 14.600 995.600 16.000 ;
        RECT 3.745 4.400 996.000 14.600 ;
        RECT 3.745 2.895 12.710 4.400 ;
        RECT 13.810 2.895 20.190 4.400 ;
        RECT 21.290 2.895 27.670 4.400 ;
        RECT 28.770 2.895 35.150 4.400 ;
        RECT 36.250 2.895 42.630 4.400 ;
        RECT 43.730 2.895 50.110 4.400 ;
        RECT 51.210 2.895 57.590 4.400 ;
        RECT 58.690 2.895 65.070 4.400 ;
        RECT 66.170 2.895 72.550 4.400 ;
        RECT 73.650 2.895 80.030 4.400 ;
        RECT 81.130 2.895 87.510 4.400 ;
        RECT 88.610 2.895 94.990 4.400 ;
        RECT 96.090 2.895 102.470 4.400 ;
        RECT 103.570 2.895 109.950 4.400 ;
        RECT 111.050 2.895 117.430 4.400 ;
        RECT 118.530 2.895 124.910 4.400 ;
        RECT 126.010 2.895 132.390 4.400 ;
        RECT 133.490 2.895 139.870 4.400 ;
        RECT 140.970 2.895 147.350 4.400 ;
        RECT 148.450 2.895 154.830 4.400 ;
        RECT 155.930 2.895 162.310 4.400 ;
        RECT 163.410 2.895 169.790 4.400 ;
        RECT 170.890 2.895 177.270 4.400 ;
        RECT 178.370 2.895 184.750 4.400 ;
        RECT 185.850 2.895 192.230 4.400 ;
        RECT 193.330 2.895 199.710 4.400 ;
        RECT 200.810 2.895 207.190 4.400 ;
        RECT 208.290 2.895 214.670 4.400 ;
        RECT 215.770 2.895 222.150 4.400 ;
        RECT 223.250 2.895 229.630 4.400 ;
        RECT 230.730 2.895 237.110 4.400 ;
        RECT 238.210 2.895 244.590 4.400 ;
        RECT 245.690 2.895 252.070 4.400 ;
        RECT 253.170 2.895 259.550 4.400 ;
        RECT 260.650 2.895 267.030 4.400 ;
        RECT 268.130 2.895 274.510 4.400 ;
        RECT 275.610 2.895 281.990 4.400 ;
        RECT 283.090 2.895 289.470 4.400 ;
        RECT 290.570 2.895 296.950 4.400 ;
        RECT 298.050 2.895 304.430 4.400 ;
        RECT 305.530 2.895 311.910 4.400 ;
        RECT 313.010 2.895 319.390 4.400 ;
        RECT 320.490 2.895 326.870 4.400 ;
        RECT 327.970 2.895 334.350 4.400 ;
        RECT 335.450 2.895 341.830 4.400 ;
        RECT 342.930 2.895 349.310 4.400 ;
        RECT 350.410 2.895 356.790 4.400 ;
        RECT 357.890 2.895 364.270 4.400 ;
        RECT 365.370 2.895 371.750 4.400 ;
        RECT 372.850 2.895 379.230 4.400 ;
        RECT 380.330 2.895 386.710 4.400 ;
        RECT 387.810 2.895 394.190 4.400 ;
        RECT 395.290 2.895 401.670 4.400 ;
        RECT 402.770 2.895 409.150 4.400 ;
        RECT 410.250 2.895 416.630 4.400 ;
        RECT 417.730 2.895 424.110 4.400 ;
        RECT 425.210 2.895 431.590 4.400 ;
        RECT 432.690 2.895 439.070 4.400 ;
        RECT 440.170 2.895 446.550 4.400 ;
        RECT 447.650 2.895 454.030 4.400 ;
        RECT 455.130 2.895 461.510 4.400 ;
        RECT 462.610 2.895 468.990 4.400 ;
        RECT 470.090 2.895 476.470 4.400 ;
        RECT 477.570 2.895 483.950 4.400 ;
        RECT 485.050 2.895 491.430 4.400 ;
        RECT 492.530 2.895 498.910 4.400 ;
        RECT 500.010 2.895 506.390 4.400 ;
        RECT 507.490 2.895 513.870 4.400 ;
        RECT 514.970 2.895 521.350 4.400 ;
        RECT 522.450 2.895 528.830 4.400 ;
        RECT 529.930 2.895 536.310 4.400 ;
        RECT 537.410 2.895 543.790 4.400 ;
        RECT 544.890 2.895 551.270 4.400 ;
        RECT 552.370 2.895 558.750 4.400 ;
        RECT 559.850 2.895 566.230 4.400 ;
        RECT 567.330 2.895 573.710 4.400 ;
        RECT 574.810 2.895 581.190 4.400 ;
        RECT 582.290 2.895 588.670 4.400 ;
        RECT 589.770 2.895 596.150 4.400 ;
        RECT 597.250 2.895 603.630 4.400 ;
        RECT 604.730 2.895 611.110 4.400 ;
        RECT 612.210 2.895 618.590 4.400 ;
        RECT 619.690 2.895 626.070 4.400 ;
        RECT 627.170 2.895 633.550 4.400 ;
        RECT 634.650 2.895 641.030 4.400 ;
        RECT 642.130 2.895 648.510 4.400 ;
        RECT 649.610 2.895 655.990 4.400 ;
        RECT 657.090 2.895 663.470 4.400 ;
        RECT 664.570 2.895 670.950 4.400 ;
        RECT 672.050 2.895 678.430 4.400 ;
        RECT 679.530 2.895 685.910 4.400 ;
        RECT 687.010 2.895 693.390 4.400 ;
        RECT 694.490 2.895 700.870 4.400 ;
        RECT 701.970 2.895 708.350 4.400 ;
        RECT 709.450 2.895 715.830 4.400 ;
        RECT 716.930 2.895 723.310 4.400 ;
        RECT 724.410 2.895 730.790 4.400 ;
        RECT 731.890 2.895 738.270 4.400 ;
        RECT 739.370 2.895 745.750 4.400 ;
        RECT 746.850 2.895 753.230 4.400 ;
        RECT 754.330 2.895 760.710 4.400 ;
        RECT 761.810 2.895 768.190 4.400 ;
        RECT 769.290 2.895 775.670 4.400 ;
        RECT 776.770 2.895 783.150 4.400 ;
        RECT 784.250 2.895 790.630 4.400 ;
        RECT 791.730 2.895 798.110 4.400 ;
        RECT 799.210 2.895 805.590 4.400 ;
        RECT 806.690 2.895 813.070 4.400 ;
        RECT 814.170 2.895 820.550 4.400 ;
        RECT 821.650 2.895 828.030 4.400 ;
        RECT 829.130 2.895 835.510 4.400 ;
        RECT 836.610 2.895 842.990 4.400 ;
        RECT 844.090 2.895 850.470 4.400 ;
        RECT 851.570 2.895 857.950 4.400 ;
        RECT 859.050 2.895 865.430 4.400 ;
        RECT 866.530 2.895 872.910 4.400 ;
        RECT 874.010 2.895 880.390 4.400 ;
        RECT 881.490 2.895 887.870 4.400 ;
        RECT 888.970 2.895 895.350 4.400 ;
        RECT 896.450 2.895 902.830 4.400 ;
        RECT 903.930 2.895 910.310 4.400 ;
        RECT 911.410 2.895 917.790 4.400 ;
        RECT 918.890 2.895 925.270 4.400 ;
        RECT 926.370 2.895 932.750 4.400 ;
        RECT 933.850 2.895 940.230 4.400 ;
        RECT 941.330 2.895 947.710 4.400 ;
        RECT 948.810 2.895 955.190 4.400 ;
        RECT 956.290 2.895 962.670 4.400 ;
        RECT 963.770 2.895 970.150 4.400 ;
        RECT 971.250 2.895 977.630 4.400 ;
        RECT 978.730 2.895 985.110 4.400 ;
        RECT 986.210 2.895 996.000 4.400 ;
      LAYER met4 ;
        RECT 54.575 36.895 97.225 772.985 ;
  END
END ntt_wb_bridge
END LIBRARY

